VERSION 5.8 ;
BUSBITCHARS "[]" ;
DIVIDERCHAR "/" ;
UNITS
    DATABASE MICRONS 1000 ;
END UNITS

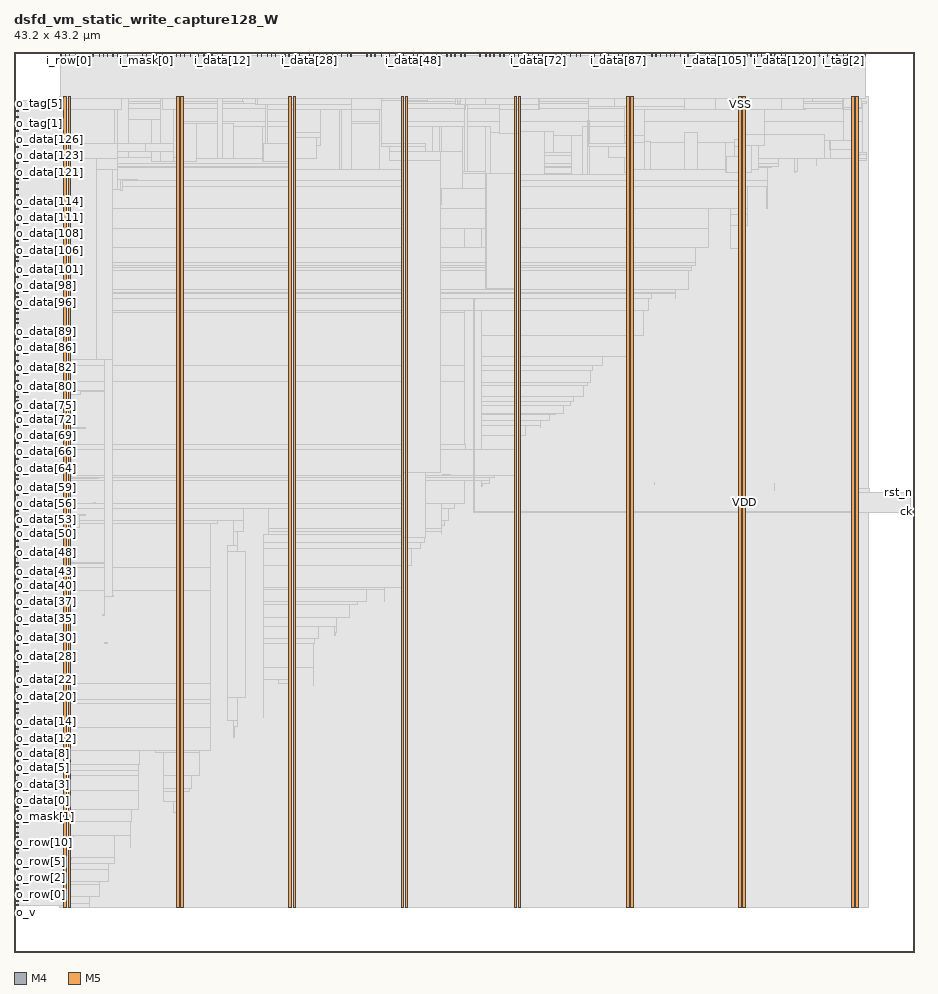
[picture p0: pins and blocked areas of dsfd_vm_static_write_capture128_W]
MACRO dsfd_vm_static_write_capture128_W
  FOREIGN dsfd_vm_static_write_capture128_W 0 0 ;
  CLASS BLOCK ;
  SIZE 43.2 BY 43.2 ;
  PIN ck
    DIRECTION INPUT ;
    USE SIGNAL ;
    PORT
      LAYER M4 ;
        RECT  43.008 21.12 43.2 21.144 ;
    END
  END ck
  PIN i_data[0]
    DIRECTION INPUT ;
    USE SIGNAL ;
    PORT
      LAYER M5 ;
        RECT  7.296 43.008 7.32 43.2 ;
    END
  END i_data[0]
  PIN i_data[100]
    DIRECTION INPUT ;
    USE SIGNAL ;
    PORT
      LAYER M5 ;
        RECT  31.968 43.008 31.992 43.2 ;
    END
  END i_data[100]
  PIN i_data[101]
    DIRECTION INPUT ;
    USE SIGNAL ;
    PORT
      LAYER M5 ;
        RECT  32.16 43.008 32.184 43.2 ;
    END
  END i_data[101]
  PIN i_data[102]
    DIRECTION INPUT ;
    USE SIGNAL ;
    PORT
      LAYER M5 ;
        RECT  32.352 43.008 32.376 43.2 ;
    END
  END i_data[102]
  PIN i_data[103]
    DIRECTION INPUT ;
    USE SIGNAL ;
    PORT
      LAYER M5 ;
        RECT  33.168 43.008 33.192 43.2 ;
    END
  END i_data[103]
  PIN i_data[104]
    DIRECTION INPUT ;
    USE SIGNAL ;
    PORT
      LAYER M5 ;
        RECT  33.36 43.008 33.384 43.2 ;
    END
  END i_data[104]
  PIN i_data[105]
    DIRECTION INPUT ;
    USE SIGNAL ;
    PORT
      LAYER M5 ;
        RECT  33.648 43.008 33.672 43.2 ;
    END
  END i_data[105]
  PIN i_data[106]
    DIRECTION INPUT ;
    USE SIGNAL ;
    PORT
      LAYER M5 ;
        RECT  33.84 43.008 33.864 43.2 ;
    END
  END i_data[106]
  PIN i_data[107]
    DIRECTION INPUT ;
    USE SIGNAL ;
    PORT
      LAYER M5 ;
        RECT  34.032 43.008 34.056 43.2 ;
    END
  END i_data[107]
  PIN i_data[108]
    DIRECTION INPUT ;
    USE SIGNAL ;
    PORT
      LAYER M5 ;
        RECT  34.32 43.008 34.344 43.2 ;
    END
  END i_data[108]
  PIN i_data[109]
    DIRECTION INPUT ;
    USE SIGNAL ;
    PORT
      LAYER M5 ;
        RECT  34.512 43.008 34.536 43.2 ;
    END
  END i_data[109]
  PIN i_data[10]
    DIRECTION INPUT ;
    USE SIGNAL ;
    PORT
      LAYER M5 ;
        RECT  9.504 43.008 9.528 43.2 ;
    END
  END i_data[10]
  PIN i_data[110]
    DIRECTION INPUT ;
    USE SIGNAL ;
    PORT
      LAYER M5 ;
        RECT  34.704 43.008 34.728 43.2 ;
    END
  END i_data[110]
  PIN i_data[111]
    DIRECTION INPUT ;
    USE SIGNAL ;
    PORT
      LAYER M5 ;
        RECT  34.992 43.008 35.016 43.2 ;
    END
  END i_data[111]
  PIN i_data[112]
    DIRECTION INPUT ;
    USE SIGNAL ;
    PORT
      LAYER M5 ;
        RECT  35.184 43.008 35.208 43.2 ;
    END
  END i_data[112]
  PIN i_data[113]
    DIRECTION INPUT ;
    USE SIGNAL ;
    PORT
      LAYER M5 ;
        RECT  35.376 43.008 35.4 43.2 ;
    END
  END i_data[113]
  PIN i_data[114]
    DIRECTION INPUT ;
    USE SIGNAL ;
    PORT
      LAYER M5 ;
        RECT  35.664 43.008 35.688 43.2 ;
    END
  END i_data[114]
  PIN i_data[115]
    DIRECTION INPUT ;
    USE SIGNAL ;
    PORT
      LAYER M5 ;
        RECT  35.856 43.008 35.88 43.2 ;
    END
  END i_data[115]
  PIN i_data[116]
    DIRECTION INPUT ;
    USE SIGNAL ;
    PORT
      LAYER M5 ;
        RECT  36.144 43.008 36.168 43.2 ;
    END
  END i_data[116]
  PIN i_data[117]
    DIRECTION INPUT ;
    USE SIGNAL ;
    PORT
      LAYER M5 ;
        RECT  36.336 43.008 36.36 43.2 ;
    END
  END i_data[117]
  PIN i_data[118]
    DIRECTION INPUT ;
    USE SIGNAL ;
    PORT
      LAYER M5 ;
        RECT  36.528 43.008 36.552 43.2 ;
    END
  END i_data[118]
  PIN i_data[119]
    DIRECTION INPUT ;
    USE SIGNAL ;
    PORT
      LAYER M5 ;
        RECT  36.816 43.008 36.84 43.2 ;
    END
  END i_data[119]
  PIN i_data[11]
    DIRECTION INPUT ;
    USE SIGNAL ;
    PORT
      LAYER M5 ;
        RECT  9.792 43.008 9.816 43.2 ;
    END
  END i_data[11]
  PIN i_data[120]
    DIRECTION INPUT ;
    USE SIGNAL ;
    PORT
      LAYER M5 ;
        RECT  37.008 43.008 37.032 43.2 ;
    END
  END i_data[120]
  PIN i_data[121]
    DIRECTION INPUT ;
    USE SIGNAL ;
    PORT
      LAYER M5 ;
        RECT  37.2 43.008 37.224 43.2 ;
    END
  END i_data[121]
  PIN i_data[122]
    DIRECTION INPUT ;
    USE SIGNAL ;
    PORT
      LAYER M5 ;
        RECT  37.488 43.008 37.512 43.2 ;
    END
  END i_data[122]
  PIN i_data[123]
    DIRECTION INPUT ;
    USE SIGNAL ;
    PORT
      LAYER M5 ;
        RECT  37.68 43.008 37.704 43.2 ;
    END
  END i_data[123]
  PIN i_data[124]
    DIRECTION INPUT ;
    USE SIGNAL ;
    PORT
      LAYER M5 ;
        RECT  37.872 43.008 37.896 43.2 ;
    END
  END i_data[124]
  PIN i_data[125]
    DIRECTION INPUT ;
    USE SIGNAL ;
    PORT
      LAYER M5 ;
        RECT  38.64 43.008 38.664 43.2 ;
    END
  END i_data[125]
  PIN i_data[126]
    DIRECTION INPUT ;
    USE SIGNAL ;
    PORT
      LAYER M5 ;
        RECT  38.832 43.008 38.856 43.2 ;
    END
  END i_data[126]
  PIN i_data[127]
    DIRECTION INPUT ;
    USE SIGNAL ;
    PORT
      LAYER M5 ;
        RECT  39.024 43.008 39.048 43.2 ;
    END
  END i_data[127]
  PIN i_data[12]
    DIRECTION INPUT ;
    USE SIGNAL ;
    PORT
      LAYER M5 ;
        RECT  9.984 43.008 10.008 43.2 ;
    END
  END i_data[12]
  PIN i_data[13]
    DIRECTION INPUT ;
    USE SIGNAL ;
    PORT
      LAYER M5 ;
        RECT  10.272 43.008 10.296 43.2 ;
    END
  END i_data[13]
  PIN i_data[14]
    DIRECTION INPUT ;
    USE SIGNAL ;
    PORT
      LAYER M5 ;
        RECT  10.464 43.008 10.488 43.2 ;
    END
  END i_data[14]
  PIN i_data[15]
    DIRECTION INPUT ;
    USE SIGNAL ;
    PORT
      LAYER M5 ;
        RECT  10.656 43.008 10.68 43.2 ;
    END
  END i_data[15]
  PIN i_data[16]
    DIRECTION INPUT ;
    USE SIGNAL ;
    PORT
      LAYER M5 ;
        RECT  10.944 43.008 10.968 43.2 ;
    END
  END i_data[16]
  PIN i_data[17]
    DIRECTION INPUT ;
    USE SIGNAL ;
    PORT
      LAYER M5 ;
        RECT  11.664 43.008 11.688 43.2 ;
    END
  END i_data[17]
  PIN i_data[18]
    DIRECTION INPUT ;
    USE SIGNAL ;
    PORT
      LAYER M5 ;
        RECT  11.856 43.008 11.88 43.2 ;
    END
  END i_data[18]
  PIN i_data[19]
    DIRECTION INPUT ;
    USE SIGNAL ;
    PORT
      LAYER M5 ;
        RECT  12.144 43.008 12.168 43.2 ;
    END
  END i_data[19]
  PIN i_data[1]
    DIRECTION INPUT ;
    USE SIGNAL ;
    PORT
      LAYER M5 ;
        RECT  7.488 43.008 7.512 43.2 ;
    END
  END i_data[1]
  PIN i_data[20]
    DIRECTION INPUT ;
    USE SIGNAL ;
    PORT
      LAYER M5 ;
        RECT  12.336 43.008 12.36 43.2 ;
    END
  END i_data[20]
  PIN i_data[21]
    DIRECTION INPUT ;
    USE SIGNAL ;
    PORT
      LAYER M5 ;
        RECT  12.528 43.008 12.552 43.2 ;
    END
  END i_data[21]
  PIN i_data[22]
    DIRECTION INPUT ;
    USE SIGNAL ;
    PORT
      LAYER M5 ;
        RECT  12.816 43.008 12.84 43.2 ;
    END
  END i_data[22]
  PIN i_data[23]
    DIRECTION INPUT ;
    USE SIGNAL ;
    PORT
      LAYER M5 ;
        RECT  13.008 43.008 13.032 43.2 ;
    END
  END i_data[23]
  PIN i_data[24]
    DIRECTION INPUT ;
    USE SIGNAL ;
    PORT
      LAYER M5 ;
        RECT  13.2 43.008 13.224 43.2 ;
    END
  END i_data[24]
  PIN i_data[25]
    DIRECTION INPUT ;
    USE SIGNAL ;
    PORT
      LAYER M5 ;
        RECT  13.488 43.008 13.512 43.2 ;
    END
  END i_data[25]
  PIN i_data[26]
    DIRECTION INPUT ;
    USE SIGNAL ;
    PORT
      LAYER M5 ;
        RECT  13.68 43.008 13.704 43.2 ;
    END
  END i_data[26]
  PIN i_data[27]
    DIRECTION INPUT ;
    USE SIGNAL ;
    PORT
      LAYER M5 ;
        RECT  13.968 43.008 13.992 43.2 ;
    END
  END i_data[27]
  PIN i_data[28]
    DIRECTION INPUT ;
    USE SIGNAL ;
    PORT
      LAYER M5 ;
        RECT  14.16 43.008 14.184 43.2 ;
    END
  END i_data[28]
  PIN i_data[29]
    DIRECTION INPUT ;
    USE SIGNAL ;
    PORT
      LAYER M5 ;
        RECT  14.352 43.008 14.376 43.2 ;
    END
  END i_data[29]
  PIN i_data[2]
    DIRECTION INPUT ;
    USE SIGNAL ;
    PORT
      LAYER M5 ;
        RECT  7.776 43.008 7.8 43.2 ;
    END
  END i_data[2]
  PIN i_data[30]
    DIRECTION INPUT ;
    USE SIGNAL ;
    PORT
      LAYER M5 ;
        RECT  14.64 43.008 14.664 43.2 ;
    END
  END i_data[30]
  PIN i_data[31]
    DIRECTION INPUT ;
    USE SIGNAL ;
    PORT
      LAYER M5 ;
        RECT  14.832 43.008 14.856 43.2 ;
    END
  END i_data[31]
  PIN i_data[32]
    DIRECTION INPUT ;
    USE SIGNAL ;
    PORT
      LAYER M5 ;
        RECT  15.024 43.008 15.048 43.2 ;
    END
  END i_data[32]
  PIN i_data[33]
    DIRECTION INPUT ;
    USE SIGNAL ;
    PORT
      LAYER M5 ;
        RECT  15.312 43.008 15.336 43.2 ;
    END
  END i_data[33]
  PIN i_data[34]
    DIRECTION INPUT ;
    USE SIGNAL ;
    PORT
      LAYER M5 ;
        RECT  15.504 43.008 15.528 43.2 ;
    END
  END i_data[34]
  PIN i_data[35]
    DIRECTION INPUT ;
    USE SIGNAL ;
    PORT
      LAYER M5 ;
        RECT  15.696 43.008 15.72 43.2 ;
    END
  END i_data[35]
  PIN i_data[36]
    DIRECTION INPUT ;
    USE SIGNAL ;
    PORT
      LAYER M5 ;
        RECT  15.984 43.008 16.008 43.2 ;
    END
  END i_data[36]
  PIN i_data[37]
    DIRECTION INPUT ;
    USE SIGNAL ;
    PORT
      LAYER M5 ;
        RECT  16.176 43.008 16.2 43.2 ;
    END
  END i_data[37]
  PIN i_data[38]
    DIRECTION INPUT ;
    USE SIGNAL ;
    PORT
      LAYER M5 ;
        RECT  16.944 43.008 16.968 43.2 ;
    END
  END i_data[38]
  PIN i_data[39]
    DIRECTION INPUT ;
    USE SIGNAL ;
    PORT
      LAYER M5 ;
        RECT  17.136 43.008 17.16 43.2 ;
    END
  END i_data[39]
  PIN i_data[3]
    DIRECTION INPUT ;
    USE SIGNAL ;
    PORT
      LAYER M5 ;
        RECT  7.968 43.008 7.992 43.2 ;
    END
  END i_data[3]
  PIN i_data[40]
    DIRECTION INPUT ;
    USE SIGNAL ;
    PORT
      LAYER M5 ;
        RECT  17.328 43.008 17.352 43.2 ;
    END
  END i_data[40]
  PIN i_data[41]
    DIRECTION INPUT ;
    USE SIGNAL ;
    PORT
      LAYER M5 ;
        RECT  17.616 43.008 17.64 43.2 ;
    END
  END i_data[41]
  PIN i_data[42]
    DIRECTION INPUT ;
    USE SIGNAL ;
    PORT
      LAYER M5 ;
        RECT  17.808 43.008 17.832 43.2 ;
    END
  END i_data[42]
  PIN i_data[43]
    DIRECTION INPUT ;
    USE SIGNAL ;
    PORT
      LAYER M5 ;
        RECT  18 43.008 18.024 43.2 ;
    END
  END i_data[43]
  PIN i_data[44]
    DIRECTION INPUT ;
    USE SIGNAL ;
    PORT
      LAYER M5 ;
        RECT  18.288 43.008 18.312 43.2 ;
    END
  END i_data[44]
  PIN i_data[45]
    DIRECTION INPUT ;
    USE SIGNAL ;
    PORT
      LAYER M5 ;
        RECT  18.48 43.008 18.504 43.2 ;
    END
  END i_data[45]
  PIN i_data[46]
    DIRECTION INPUT ;
    USE SIGNAL ;
    PORT
      LAYER M5 ;
        RECT  18.672 43.008 18.696 43.2 ;
    END
  END i_data[46]
  PIN i_data[47]
    DIRECTION INPUT ;
    USE SIGNAL ;
    PORT
      LAYER M5 ;
        RECT  18.96 43.008 18.984 43.2 ;
    END
  END i_data[47]
  PIN i_data[48]
    DIRECTION INPUT ;
    USE SIGNAL ;
    PORT
      LAYER M5 ;
        RECT  19.152 43.008 19.176 43.2 ;
    END
  END i_data[48]
  PIN i_data[49]
    DIRECTION INPUT ;
    USE SIGNAL ;
    PORT
      LAYER M5 ;
        RECT  19.344 43.008 19.368 43.2 ;
    END
  END i_data[49]
  PIN i_data[4]
    DIRECTION INPUT ;
    USE SIGNAL ;
    PORT
      LAYER M5 ;
        RECT  8.16 43.008 8.184 43.2 ;
    END
  END i_data[4]
  PIN i_data[50]
    DIRECTION INPUT ;
    USE SIGNAL ;
    PORT
      LAYER M5 ;
        RECT  19.632 43.008 19.656 43.2 ;
    END
  END i_data[50]
  PIN i_data[51]
    DIRECTION INPUT ;
    USE SIGNAL ;
    PORT
      LAYER M5 ;
        RECT  19.824 43.008 19.848 43.2 ;
    END
  END i_data[51]
  PIN i_data[52]
    DIRECTION INPUT ;
    USE SIGNAL ;
    PORT
      LAYER M5 ;
        RECT  20.112 43.008 20.136 43.2 ;
    END
  END i_data[52]
  PIN i_data[53]
    DIRECTION INPUT ;
    USE SIGNAL ;
    PORT
      LAYER M5 ;
        RECT  20.304 43.008 20.328 43.2 ;
    END
  END i_data[53]
  PIN i_data[54]
    DIRECTION INPUT ;
    USE SIGNAL ;
    PORT
      LAYER M5 ;
        RECT  20.496 43.008 20.52 43.2 ;
    END
  END i_data[54]
  PIN i_data[55]
    DIRECTION INPUT ;
    USE SIGNAL ;
    PORT
      LAYER M5 ;
        RECT  20.784 43.008 20.808 43.2 ;
    END
  END i_data[55]
  PIN i_data[56]
    DIRECTION INPUT ;
    USE SIGNAL ;
    PORT
      LAYER M5 ;
        RECT  20.976 43.008 21 43.2 ;
    END
  END i_data[56]
  PIN i_data[57]
    DIRECTION INPUT ;
    USE SIGNAL ;
    PORT
      LAYER M5 ;
        RECT  21.168 43.008 21.192 43.2 ;
    END
  END i_data[57]
  PIN i_data[58]
    DIRECTION INPUT ;
    USE SIGNAL ;
    PORT
      LAYER M5 ;
        RECT  21.456 43.008 21.48 43.2 ;
    END
  END i_data[58]
  PIN i_data[59]
    DIRECTION INPUT ;
    USE SIGNAL ;
    PORT
      LAYER M5 ;
        RECT  21.648 43.008 21.672 43.2 ;
    END
  END i_data[59]
  PIN i_data[5]
    DIRECTION INPUT ;
    USE SIGNAL ;
    PORT
      LAYER M5 ;
        RECT  8.448 43.008 8.472 43.2 ;
    END
  END i_data[5]
  PIN i_data[60]
    DIRECTION INPUT ;
    USE SIGNAL ;
    PORT
      LAYER M5 ;
        RECT  22.368 43.008 22.392 43.2 ;
    END
  END i_data[60]
  PIN i_data[61]
    DIRECTION INPUT ;
    USE SIGNAL ;
    PORT
      LAYER M5 ;
        RECT  22.656 43.008 22.68 43.2 ;
    END
  END i_data[61]
  PIN i_data[62]
    DIRECTION INPUT ;
    USE SIGNAL ;
    PORT
      LAYER M5 ;
        RECT  22.848 43.008 22.872 43.2 ;
    END
  END i_data[62]
  PIN i_data[63]
    DIRECTION INPUT ;
    USE SIGNAL ;
    PORT
      LAYER M5 ;
        RECT  23.04 43.008 23.064 43.2 ;
    END
  END i_data[63]
  PIN i_data[64]
    DIRECTION INPUT ;
    USE SIGNAL ;
    PORT
      LAYER M5 ;
        RECT  23.328 43.008 23.352 43.2 ;
    END
  END i_data[64]
  PIN i_data[65]
    DIRECTION INPUT ;
    USE SIGNAL ;
    PORT
      LAYER M5 ;
        RECT  23.52 43.008 23.544 43.2 ;
    END
  END i_data[65]
  PIN i_data[66]
    DIRECTION INPUT ;
    USE SIGNAL ;
    PORT
      LAYER M5 ;
        RECT  23.808 43.008 23.832 43.2 ;
    END
  END i_data[66]
  PIN i_data[67]
    DIRECTION INPUT ;
    USE SIGNAL ;
    PORT
      LAYER M5 ;
        RECT  24 43.008 24.024 43.2 ;
    END
  END i_data[67]
  PIN i_data[68]
    DIRECTION INPUT ;
    USE SIGNAL ;
    PORT
      LAYER M5 ;
        RECT  24.192 43.008 24.216 43.2 ;
    END
  END i_data[68]
  PIN i_data[69]
    DIRECTION INPUT ;
    USE SIGNAL ;
    PORT
      LAYER M5 ;
        RECT  24.48 43.008 24.504 43.2 ;
    END
  END i_data[69]
  PIN i_data[6]
    DIRECTION INPUT ;
    USE SIGNAL ;
    PORT
      LAYER M5 ;
        RECT  8.64 43.008 8.664 43.2 ;
    END
  END i_data[6]
  PIN i_data[70]
    DIRECTION INPUT ;
    USE SIGNAL ;
    PORT
      LAYER M5 ;
        RECT  24.672 43.008 24.696 43.2 ;
    END
  END i_data[70]
  PIN i_data[71]
    DIRECTION INPUT ;
    USE SIGNAL ;
    PORT
      LAYER M5 ;
        RECT  24.864 43.008 24.888 43.2 ;
    END
  END i_data[71]
  PIN i_data[72]
    DIRECTION INPUT ;
    USE SIGNAL ;
    PORT
      LAYER M5 ;
        RECT  25.152 43.008 25.176 43.2 ;
    END
  END i_data[72]
  PIN i_data[73]
    DIRECTION INPUT ;
    USE SIGNAL ;
    PORT
      LAYER M5 ;
        RECT  25.344 43.008 25.368 43.2 ;
    END
  END i_data[73]
  PIN i_data[74]
    DIRECTION INPUT ;
    USE SIGNAL ;
    PORT
      LAYER M5 ;
        RECT  25.536 43.008 25.56 43.2 ;
    END
  END i_data[74]
  PIN i_data[75]
    DIRECTION INPUT ;
    USE SIGNAL ;
    PORT
      LAYER M5 ;
        RECT  25.824 43.008 25.848 43.2 ;
    END
  END i_data[75]
  PIN i_data[76]
    DIRECTION INPUT ;
    USE SIGNAL ;
    PORT
      LAYER M5 ;
        RECT  26.016 43.008 26.04 43.2 ;
    END
  END i_data[76]
  PIN i_data[77]
    DIRECTION INPUT ;
    USE SIGNAL ;
    PORT
      LAYER M5 ;
        RECT  26.304 43.008 26.328 43.2 ;
    END
  END i_data[77]
  PIN i_data[78]
    DIRECTION INPUT ;
    USE SIGNAL ;
    PORT
      LAYER M5 ;
        RECT  26.496 43.008 26.52 43.2 ;
    END
  END i_data[78]
  PIN i_data[79]
    DIRECTION INPUT ;
    USE SIGNAL ;
    PORT
      LAYER M5 ;
        RECT  26.688 43.008 26.712 43.2 ;
    END
  END i_data[79]
  PIN i_data[7]
    DIRECTION INPUT ;
    USE SIGNAL ;
    PORT
      LAYER M5 ;
        RECT  8.832 43.008 8.856 43.2 ;
    END
  END i_data[7]
  PIN i_data[80]
    DIRECTION INPUT ;
    USE SIGNAL ;
    PORT
      LAYER M5 ;
        RECT  26.976 43.008 27 43.2 ;
    END
  END i_data[80]
  PIN i_data[81]
    DIRECTION INPUT ;
    USE SIGNAL ;
    PORT
      LAYER M5 ;
        RECT  27.168 43.008 27.192 43.2 ;
    END
  END i_data[81]
  PIN i_data[82]
    DIRECTION INPUT ;
    USE SIGNAL ;
    PORT
      LAYER M5 ;
        RECT  27.84 43.008 27.864 43.2 ;
    END
  END i_data[82]
  PIN i_data[83]
    DIRECTION INPUT ;
    USE SIGNAL ;
    PORT
      LAYER M5 ;
        RECT  28.128 43.008 28.152 43.2 ;
    END
  END i_data[83]
  PIN i_data[84]
    DIRECTION INPUT ;
    USE SIGNAL ;
    PORT
      LAYER M5 ;
        RECT  28.32 43.008 28.344 43.2 ;
    END
  END i_data[84]
  PIN i_data[85]
    DIRECTION INPUT ;
    USE SIGNAL ;
    PORT
      LAYER M5 ;
        RECT  28.512 43.008 28.536 43.2 ;
    END
  END i_data[85]
  PIN i_data[86]
    DIRECTION INPUT ;
    USE SIGNAL ;
    PORT
      LAYER M5 ;
        RECT  28.8 43.008 28.824 43.2 ;
    END
  END i_data[86]
  PIN i_data[87]
    DIRECTION INPUT ;
    USE SIGNAL ;
    PORT
      LAYER M5 ;
        RECT  28.992 43.008 29.016 43.2 ;
    END
  END i_data[87]
  PIN i_data[88]
    DIRECTION INPUT ;
    USE SIGNAL ;
    PORT
      LAYER M5 ;
        RECT  29.184 43.008 29.208 43.2 ;
    END
  END i_data[88]
  PIN i_data[89]
    DIRECTION INPUT ;
    USE SIGNAL ;
    PORT
      LAYER M5 ;
        RECT  29.472 43.008 29.496 43.2 ;
    END
  END i_data[89]
  PIN i_data[8]
    DIRECTION INPUT ;
    USE SIGNAL ;
    PORT
      LAYER M5 ;
        RECT  9.12 43.008 9.144 43.2 ;
    END
  END i_data[8]
  PIN i_data[90]
    DIRECTION INPUT ;
    USE SIGNAL ;
    PORT
      LAYER M5 ;
        RECT  29.664 43.008 29.688 43.2 ;
    END
  END i_data[90]
  PIN i_data[91]
    DIRECTION INPUT ;
    USE SIGNAL ;
    PORT
      LAYER M5 ;
        RECT  29.952 43.008 29.976 43.2 ;
    END
  END i_data[91]
  PIN i_data[92]
    DIRECTION INPUT ;
    USE SIGNAL ;
    PORT
      LAYER M5 ;
        RECT  30.144 43.008 30.168 43.2 ;
    END
  END i_data[92]
  PIN i_data[93]
    DIRECTION INPUT ;
    USE SIGNAL ;
    PORT
      LAYER M5 ;
        RECT  30.336 43.008 30.36 43.2 ;
    END
  END i_data[93]
  PIN i_data[94]
    DIRECTION INPUT ;
    USE SIGNAL ;
    PORT
      LAYER M5 ;
        RECT  30.624 43.008 30.648 43.2 ;
    END
  END i_data[94]
  PIN i_data[95]
    DIRECTION INPUT ;
    USE SIGNAL ;
    PORT
      LAYER M5 ;
        RECT  30.816 43.008 30.84 43.2 ;
    END
  END i_data[95]
  PIN i_data[96]
    DIRECTION INPUT ;
    USE SIGNAL ;
    PORT
      LAYER M5 ;
        RECT  31.008 43.008 31.032 43.2 ;
    END
  END i_data[96]
  PIN i_data[97]
    DIRECTION INPUT ;
    USE SIGNAL ;
    PORT
      LAYER M5 ;
        RECT  31.296 43.008 31.32 43.2 ;
    END
  END i_data[97]
  PIN i_data[98]
    DIRECTION INPUT ;
    USE SIGNAL ;
    PORT
      LAYER M5 ;
        RECT  31.488 43.008 31.512 43.2 ;
    END
  END i_data[98]
  PIN i_data[99]
    DIRECTION INPUT ;
    USE SIGNAL ;
    PORT
      LAYER M5 ;
        RECT  31.68 43.008 31.704 43.2 ;
    END
  END i_data[99]
  PIN i_data[9]
    DIRECTION INPUT ;
    USE SIGNAL ;
    PORT
      LAYER M5 ;
        RECT  9.312 43.008 9.336 43.2 ;
    END
  END i_data[9]
  PIN i_mask[0]
    DIRECTION INPUT ;
    USE SIGNAL ;
    PORT
      LAYER M5 ;
        RECT  6.336 43.008 6.36 43.2 ;
    END
  END i_mask[0]
  PIN i_mask[1]
    DIRECTION INPUT ;
    USE SIGNAL ;
    PORT
      LAYER M5 ;
        RECT  6.624 43.008 6.648 43.2 ;
    END
  END i_mask[1]
  PIN i_mask[2]
    DIRECTION INPUT ;
    USE SIGNAL ;
    PORT
      LAYER M5 ;
        RECT  6.816 43.008 6.84 43.2 ;
    END
  END i_mask[2]
  PIN i_mask[3]
    DIRECTION INPUT ;
    USE SIGNAL ;
    PORT
      LAYER M5 ;
        RECT  7.104 43.008 7.128 43.2 ;
    END
  END i_mask[3]
  PIN i_row[0]
    DIRECTION INPUT ;
    USE SIGNAL ;
    PORT
      LAYER M5 ;
        RECT  2.64 43.008 2.664 43.2 ;
    END
  END i_row[0]
  PIN i_row[10]
    DIRECTION INPUT ;
    USE SIGNAL ;
    PORT
      LAYER M5 ;
        RECT  4.944 43.008 4.968 43.2 ;
    END
  END i_row[10]
  PIN i_row[11]
    DIRECTION INPUT ;
    USE SIGNAL ;
    PORT
      LAYER M5 ;
        RECT  5.136 43.008 5.16 43.2 ;
    END
  END i_row[11]
  PIN i_row[12]
    DIRECTION INPUT ;
    USE SIGNAL ;
    PORT
      LAYER M5 ;
        RECT  5.424 43.008 5.448 43.2 ;
    END
  END i_row[12]
  PIN i_row[13]
    DIRECTION INPUT ;
    USE SIGNAL ;
    PORT
      LAYER M5 ;
        RECT  6.144 43.008 6.168 43.2 ;
    END
  END i_row[13]
  PIN i_row[1]
    DIRECTION INPUT ;
    USE SIGNAL ;
    PORT
      LAYER M5 ;
        RECT  2.928 43.008 2.952 43.2 ;
    END
  END i_row[1]
  PIN i_row[2]
    DIRECTION INPUT ;
    USE SIGNAL ;
    PORT
      LAYER M5 ;
        RECT  3.12 43.008 3.144 43.2 ;
    END
  END i_row[2]
  PIN i_row[3]
    DIRECTION INPUT ;
    USE SIGNAL ;
    PORT
      LAYER M5 ;
        RECT  3.312 43.008 3.336 43.2 ;
    END
  END i_row[3]
  PIN i_row[4]
    DIRECTION INPUT ;
    USE SIGNAL ;
    PORT
      LAYER M5 ;
        RECT  3.6 43.008 3.624 43.2 ;
    END
  END i_row[4]
  PIN i_row[5]
    DIRECTION INPUT ;
    USE SIGNAL ;
    PORT
      LAYER M5 ;
        RECT  3.792 43.008 3.816 43.2 ;
    END
  END i_row[5]
  PIN i_row[6]
    DIRECTION INPUT ;
    USE SIGNAL ;
    PORT
      LAYER M5 ;
        RECT  4.08 43.008 4.104 43.2 ;
    END
  END i_row[6]
  PIN i_row[7]
    DIRECTION INPUT ;
    USE SIGNAL ;
    PORT
      LAYER M5 ;
        RECT  4.272 43.008 4.296 43.2 ;
    END
  END i_row[7]
  PIN i_row[8]
    DIRECTION INPUT ;
    USE SIGNAL ;
    PORT
      LAYER M5 ;
        RECT  4.464 43.008 4.488 43.2 ;
    END
  END i_row[8]
  PIN i_row[9]
    DIRECTION INPUT ;
    USE SIGNAL ;
    PORT
      LAYER M5 ;
        RECT  4.752 43.008 4.776 43.2 ;
    END
  END i_row[9]
  PIN i_tag[0]
    DIRECTION INPUT ;
    USE SIGNAL ;
    PORT
      LAYER M5 ;
        RECT  39.312 43.008 39.336 43.2 ;
    END
  END i_tag[0]
  PIN i_tag[1]
    DIRECTION INPUT ;
    USE SIGNAL ;
    PORT
      LAYER M5 ;
        RECT  39.504 43.008 39.528 43.2 ;
    END
  END i_tag[1]
  PIN i_tag[2]
    DIRECTION INPUT ;
    USE SIGNAL ;
    PORT
      LAYER M5 ;
        RECT  39.792 43.008 39.816 43.2 ;
    END
  END i_tag[2]
  PIN i_tag[3]
    DIRECTION INPUT ;
    USE SIGNAL ;
    PORT
      LAYER M5 ;
        RECT  39.984 43.008 40.008 43.2 ;
    END
  END i_tag[3]
  PIN i_tag[4]
    DIRECTION INPUT ;
    USE SIGNAL ;
    PORT
      LAYER M5 ;
        RECT  40.176 43.008 40.2 43.2 ;
    END
  END i_tag[4]
  PIN i_tag[5]
    DIRECTION INPUT ;
    USE SIGNAL ;
    PORT
      LAYER M5 ;
        RECT  40.464 43.008 40.488 43.2 ;
    END
  END i_tag[5]
  PIN i_tag[6]
    DIRECTION INPUT ;
    USE SIGNAL ;
    PORT
      LAYER M5 ;
        RECT  40.656 43.008 40.68 43.2 ;
    END
  END i_tag[6]
  PIN i_tag[7]
    DIRECTION INPUT ;
    USE SIGNAL ;
    PORT
      LAYER M5 ;
        RECT  40.848 43.008 40.872 43.2 ;
    END
  END i_tag[7]
  PIN i_v
    DIRECTION INPUT ;
    USE SIGNAL ;
    PORT
      LAYER M5 ;
        RECT  2.256 43.008 2.28 43.2 ;
    END
  END i_v
  PIN i_we
    DIRECTION INPUT ;
    USE SIGNAL ;
    PORT
      LAYER M5 ;
        RECT  2.448 43.008 2.472 43.2 ;
    END
  END i_we
  PIN o_data[0]
    DIRECTION OUTPUT ;
    USE SIGNAL ;
    PORT
      LAYER M4 ;
        RECT  0 7.248 0.192 7.272 ;
    END
  END o_data[0]
  PIN o_data[100]
    DIRECTION OUTPUT ;
    USE SIGNAL ;
    PORT
      LAYER M4 ;
        RECT  0 32.112 0.192 32.136 ;
    END
  END o_data[100]
  PIN o_data[101]
    DIRECTION OUTPUT ;
    USE SIGNAL ;
    PORT
      LAYER M4 ;
        RECT  0 32.4 0.192 32.424 ;
    END
  END o_data[101]
  PIN o_data[102]
    DIRECTION OUTPUT ;
    USE SIGNAL ;
    PORT
      LAYER M4 ;
        RECT  0 32.688 0.192 32.712 ;
    END
  END o_data[102]
  PIN o_data[103]
    DIRECTION OUTPUT ;
    USE SIGNAL ;
    PORT
      LAYER M4 ;
        RECT  0 32.88 0.192 32.904 ;
    END
  END o_data[103]
  PIN o_data[104]
    DIRECTION OUTPUT ;
    USE SIGNAL ;
    PORT
      LAYER M4 ;
        RECT  0 33.168 0.192 33.192 ;
    END
  END o_data[104]
  PIN o_data[105]
    DIRECTION OUTPUT ;
    USE SIGNAL ;
    PORT
      LAYER M4 ;
        RECT  0 33.36 0.192 33.384 ;
    END
  END o_data[105]
  PIN o_data[106]
    DIRECTION OUTPUT ;
    USE SIGNAL ;
    PORT
      LAYER M4 ;
        RECT  0 33.648 0.192 33.672 ;
    END
  END o_data[106]
  PIN o_data[107]
    DIRECTION OUTPUT ;
    USE SIGNAL ;
    PORT
      LAYER M4 ;
        RECT  0 33.936 0.192 33.96 ;
    END
  END o_data[107]
  PIN o_data[108]
    DIRECTION OUTPUT ;
    USE SIGNAL ;
    PORT
      LAYER M4 ;
        RECT  0 34.128 0.192 34.152 ;
    END
  END o_data[108]
  PIN o_data[109]
    DIRECTION OUTPUT ;
    USE SIGNAL ;
    PORT
      LAYER M4 ;
        RECT  0 34.416 0.192 34.44 ;
    END
  END o_data[109]
  PIN o_data[10]
    DIRECTION OUTPUT ;
    USE SIGNAL ;
    PORT
      LAYER M4 ;
        RECT  0 9.744 0.192 9.768 ;
    END
  END o_data[10]
  PIN o_data[110]
    DIRECTION OUTPUT ;
    USE SIGNAL ;
    PORT
      LAYER M4 ;
        RECT  0 34.608 0.192 34.632 ;
    END
  END o_data[110]
  PIN o_data[111]
    DIRECTION OUTPUT ;
    USE SIGNAL ;
    PORT
      LAYER M4 ;
        RECT  0 34.896 0.192 34.92 ;
    END
  END o_data[111]
  PIN o_data[112]
    DIRECTION OUTPUT ;
    USE SIGNAL ;
    PORT
      LAYER M4 ;
        RECT  0 35.088 0.192 35.112 ;
    END
  END o_data[112]
  PIN o_data[113]
    DIRECTION OUTPUT ;
    USE SIGNAL ;
    PORT
      LAYER M4 ;
        RECT  0 35.376 0.192 35.4 ;
    END
  END o_data[113]
  PIN o_data[114]
    DIRECTION OUTPUT ;
    USE SIGNAL ;
    PORT
      LAYER M4 ;
        RECT  0 35.664 0.192 35.688 ;
    END
  END o_data[114]
  PIN o_data[115]
    DIRECTION OUTPUT ;
    USE SIGNAL ;
    PORT
      LAYER M4 ;
        RECT  0 35.856 0.192 35.88 ;
    END
  END o_data[115]
  PIN o_data[116]
    DIRECTION OUTPUT ;
    USE SIGNAL ;
    PORT
      LAYER M4 ;
        RECT  0 36.144 0.192 36.168 ;
    END
  END o_data[116]
  PIN o_data[117]
    DIRECTION OUTPUT ;
    USE SIGNAL ;
    PORT
      LAYER M4 ;
        RECT  0 36.336 0.192 36.36 ;
    END
  END o_data[117]
  PIN o_data[118]
    DIRECTION OUTPUT ;
    USE SIGNAL ;
    PORT
      LAYER M4 ;
        RECT  0 36.624 0.192 36.648 ;
    END
  END o_data[118]
  PIN o_data[119]
    DIRECTION OUTPUT ;
    USE SIGNAL ;
    PORT
      LAYER M4 ;
        RECT  0 36.912 0.192 36.936 ;
    END
  END o_data[119]
  PIN o_data[11]
    DIRECTION OUTPUT ;
    USE SIGNAL ;
    PORT
      LAYER M4 ;
        RECT  0 9.936 0.192 9.96 ;
    END
  END o_data[11]
  PIN o_data[120]
    DIRECTION OUTPUT ;
    USE SIGNAL ;
    PORT
      LAYER M4 ;
        RECT  0 37.104 0.192 37.128 ;
    END
  END o_data[120]
  PIN o_data[121]
    DIRECTION OUTPUT ;
    USE SIGNAL ;
    PORT
      LAYER M4 ;
        RECT  0 37.392 0.192 37.416 ;
    END
  END o_data[121]
  PIN o_data[122]
    DIRECTION OUTPUT ;
    USE SIGNAL ;
    PORT
      LAYER M4 ;
        RECT  0 37.584 0.192 37.608 ;
    END
  END o_data[122]
  PIN o_data[123]
    DIRECTION OUTPUT ;
    USE SIGNAL ;
    PORT
      LAYER M4 ;
        RECT  0 37.872 0.192 37.896 ;
    END
  END o_data[123]
  PIN o_data[124]
    DIRECTION OUTPUT ;
    USE SIGNAL ;
    PORT
      LAYER M4 ;
        RECT  0 38.16 0.192 38.184 ;
    END
  END o_data[124]
  PIN o_data[125]
    DIRECTION OUTPUT ;
    USE SIGNAL ;
    PORT
      LAYER M4 ;
        RECT  0 38.352 0.192 38.376 ;
    END
  END o_data[125]
  PIN o_data[126]
    DIRECTION OUTPUT ;
    USE SIGNAL ;
    PORT
      LAYER M4 ;
        RECT  0 38.64 0.192 38.664 ;
    END
  END o_data[126]
  PIN o_data[127]
    DIRECTION OUTPUT ;
    USE SIGNAL ;
    PORT
      LAYER M4 ;
        RECT  0 38.832 0.192 38.856 ;
    END
  END o_data[127]
  PIN o_data[12]
    DIRECTION OUTPUT ;
    USE SIGNAL ;
    PORT
      LAYER M4 ;
        RECT  0 10.224 0.192 10.248 ;
    END
  END o_data[12]
  PIN o_data[13]
    DIRECTION OUTPUT ;
    USE SIGNAL ;
    PORT
      LAYER M4 ;
        RECT  0 10.416 0.192 10.44 ;
    END
  END o_data[13]
  PIN o_data[14]
    DIRECTION OUTPUT ;
    USE SIGNAL ;
    PORT
      LAYER M4 ;
        RECT  0 10.704 0.192 10.728 ;
    END
  END o_data[14]
  PIN o_data[15]
    DIRECTION OUTPUT ;
    USE SIGNAL ;
    PORT
      LAYER M4 ;
        RECT  0 10.992 0.192 11.016 ;
    END
  END o_data[15]
  PIN o_data[16]
    DIRECTION OUTPUT ;
    USE SIGNAL ;
    PORT
      LAYER M4 ;
        RECT  0 11.184 0.192 11.208 ;
    END
  END o_data[16]
  PIN o_data[17]
    DIRECTION OUTPUT ;
    USE SIGNAL ;
    PORT
      LAYER M4 ;
        RECT  0 11.472 0.192 11.496 ;
    END
  END o_data[17]
  PIN o_data[18]
    DIRECTION OUTPUT ;
    USE SIGNAL ;
    PORT
      LAYER M4 ;
        RECT  0 11.664 0.192 11.688 ;
    END
  END o_data[18]
  PIN o_data[19]
    DIRECTION OUTPUT ;
    USE SIGNAL ;
    PORT
      LAYER M4 ;
        RECT  0 11.952 0.192 11.976 ;
    END
  END o_data[19]
  PIN o_data[1]
    DIRECTION OUTPUT ;
    USE SIGNAL ;
    PORT
      LAYER M4 ;
        RECT  0 7.44 0.192 7.464 ;
    END
  END o_data[1]
  PIN o_data[20]
    DIRECTION OUTPUT ;
    USE SIGNAL ;
    PORT
      LAYER M4 ;
        RECT  0 12.24 0.192 12.264 ;
    END
  END o_data[20]
  PIN o_data[21]
    DIRECTION OUTPUT ;
    USE SIGNAL ;
    PORT
      LAYER M4 ;
        RECT  0 12.432 0.192 12.456 ;
    END
  END o_data[21]
  PIN o_data[22]
    DIRECTION OUTPUT ;
    USE SIGNAL ;
    PORT
      LAYER M4 ;
        RECT  0 12.72 0.192 12.744 ;
    END
  END o_data[22]
  PIN o_data[23]
    DIRECTION OUTPUT ;
    USE SIGNAL ;
    PORT
      LAYER M4 ;
        RECT  0 12.912 0.192 12.936 ;
    END
  END o_data[23]
  PIN o_data[24]
    DIRECTION OUTPUT ;
    USE SIGNAL ;
    PORT
      LAYER M4 ;
        RECT  0 13.2 0.192 13.224 ;
    END
  END o_data[24]
  PIN o_data[25]
    DIRECTION OUTPUT ;
    USE SIGNAL ;
    PORT
      LAYER M4 ;
        RECT  0 13.488 0.192 13.512 ;
    END
  END o_data[25]
  PIN o_data[26]
    DIRECTION OUTPUT ;
    USE SIGNAL ;
    PORT
      LAYER M4 ;
        RECT  0 13.68 0.192 13.704 ;
    END
  END o_data[26]
  PIN o_data[27]
    DIRECTION OUTPUT ;
    USE SIGNAL ;
    PORT
      LAYER M4 ;
        RECT  0 13.968 0.192 13.992 ;
    END
  END o_data[27]
  PIN o_data[28]
    DIRECTION OUTPUT ;
    USE SIGNAL ;
    PORT
      LAYER M4 ;
        RECT  0 14.16 0.192 14.184 ;
    END
  END o_data[28]
  PIN o_data[29]
    DIRECTION OUTPUT ;
    USE SIGNAL ;
    PORT
      LAYER M4 ;
        RECT  0 14.448 0.192 14.472 ;
    END
  END o_data[29]
  PIN o_data[2]
    DIRECTION OUTPUT ;
    USE SIGNAL ;
    PORT
      LAYER M4 ;
        RECT  0 7.728 0.192 7.752 ;
    END
  END o_data[2]
  PIN o_data[30]
    DIRECTION OUTPUT ;
    USE SIGNAL ;
    PORT
      LAYER M4 ;
        RECT  0 14.736 0.192 14.76 ;
    END
  END o_data[30]
  PIN o_data[31]
    DIRECTION OUTPUT ;
    USE SIGNAL ;
    PORT
      LAYER M4 ;
        RECT  0 14.928 0.192 14.952 ;
    END
  END o_data[31]
  PIN o_data[32]
    DIRECTION OUTPUT ;
    USE SIGNAL ;
    PORT
      LAYER M4 ;
        RECT  0 15.216 0.192 15.24 ;
    END
  END o_data[32]
  PIN o_data[33]
    DIRECTION OUTPUT ;
    USE SIGNAL ;
    PORT
      LAYER M4 ;
        RECT  0 15.408 0.192 15.432 ;
    END
  END o_data[33]
  PIN o_data[34]
    DIRECTION OUTPUT ;
    USE SIGNAL ;
    PORT
      LAYER M4 ;
        RECT  0 15.696 0.192 15.72 ;
    END
  END o_data[34]
  PIN o_data[35]
    DIRECTION OUTPUT ;
    USE SIGNAL ;
    PORT
      LAYER M4 ;
        RECT  0 15.984 0.192 16.008 ;
    END
  END o_data[35]
  PIN o_data[36]
    DIRECTION OUTPUT ;
    USE SIGNAL ;
    PORT
      LAYER M4 ;
        RECT  0 16.176 0.192 16.2 ;
    END
  END o_data[36]
  PIN o_data[37]
    DIRECTION OUTPUT ;
    USE SIGNAL ;
    PORT
      LAYER M4 ;
        RECT  0 16.464 0.192 16.488 ;
    END
  END o_data[37]
  PIN o_data[38]
    DIRECTION OUTPUT ;
    USE SIGNAL ;
    PORT
      LAYER M4 ;
        RECT  0 16.656 0.192 16.68 ;
    END
  END o_data[38]
  PIN o_data[39]
    DIRECTION OUTPUT ;
    USE SIGNAL ;
    PORT
      LAYER M4 ;
        RECT  0 16.944 0.192 16.968 ;
    END
  END o_data[39]
  PIN o_data[3]
    DIRECTION OUTPUT ;
    USE SIGNAL ;
    PORT
      LAYER M4 ;
        RECT  0 8.016 0.192 8.04 ;
    END
  END o_data[3]
  PIN o_data[40]
    DIRECTION OUTPUT ;
    USE SIGNAL ;
    PORT
      LAYER M4 ;
        RECT  0 17.232 0.192 17.256 ;
    END
  END o_data[40]
  PIN o_data[41]
    DIRECTION OUTPUT ;
    USE SIGNAL ;
    PORT
      LAYER M4 ;
        RECT  0 17.424 0.192 17.448 ;
    END
  END o_data[41]
  PIN o_data[42]
    DIRECTION OUTPUT ;
    USE SIGNAL ;
    PORT
      LAYER M4 ;
        RECT  0 17.712 0.192 17.736 ;
    END
  END o_data[42]
  PIN o_data[43]
    DIRECTION OUTPUT ;
    USE SIGNAL ;
    PORT
      LAYER M4 ;
        RECT  0 17.904 0.192 17.928 ;
    END
  END o_data[43]
  PIN o_data[44]
    DIRECTION OUTPUT ;
    USE SIGNAL ;
    PORT
      LAYER M4 ;
        RECT  0 18.192 0.192 18.216 ;
    END
  END o_data[44]
  PIN o_data[45]
    DIRECTION OUTPUT ;
    USE SIGNAL ;
    PORT
      LAYER M4 ;
        RECT  0 18.48 0.192 18.504 ;
    END
  END o_data[45]
  PIN o_data[46]
    DIRECTION OUTPUT ;
    USE SIGNAL ;
    PORT
      LAYER M4 ;
        RECT  0 18.672 0.192 18.696 ;
    END
  END o_data[46]
  PIN o_data[47]
    DIRECTION OUTPUT ;
    USE SIGNAL ;
    PORT
      LAYER M4 ;
        RECT  0 18.96 0.192 18.984 ;
    END
  END o_data[47]
  PIN o_data[48]
    DIRECTION OUTPUT ;
    USE SIGNAL ;
    PORT
      LAYER M4 ;
        RECT  0 19.152 0.192 19.176 ;
    END
  END o_data[48]
  PIN o_data[49]
    DIRECTION OUTPUT ;
    USE SIGNAL ;
    PORT
      LAYER M4 ;
        RECT  0 19.44 0.192 19.464 ;
    END
  END o_data[49]
  PIN o_data[4]
    DIRECTION OUTPUT ;
    USE SIGNAL ;
    PORT
      LAYER M4 ;
        RECT  0 8.208 0.192 8.232 ;
    END
  END o_data[4]
  PIN o_data[50]
    DIRECTION OUTPUT ;
    USE SIGNAL ;
    PORT
      LAYER M4 ;
        RECT  0 19.728 0.192 19.752 ;
    END
  END o_data[50]
  PIN o_data[51]
    DIRECTION OUTPUT ;
    USE SIGNAL ;
    PORT
      LAYER M4 ;
        RECT  0 19.92 0.192 19.944 ;
    END
  END o_data[51]
  PIN o_data[52]
    DIRECTION OUTPUT ;
    USE SIGNAL ;
    PORT
      LAYER M4 ;
        RECT  0 20.208 0.192 20.232 ;
    END
  END o_data[52]
  PIN o_data[53]
    DIRECTION OUTPUT ;
    USE SIGNAL ;
    PORT
      LAYER M4 ;
        RECT  0 20.4 0.192 20.424 ;
    END
  END o_data[53]
  PIN o_data[54]
    DIRECTION OUTPUT ;
    USE SIGNAL ;
    PORT
      LAYER M4 ;
        RECT  0 20.688 0.192 20.712 ;
    END
  END o_data[54]
  PIN o_data[55]
    DIRECTION OUTPUT ;
    USE SIGNAL ;
    PORT
      LAYER M4 ;
        RECT  0 20.976 0.192 21 ;
    END
  END o_data[55]
  PIN o_data[56]
    DIRECTION OUTPUT ;
    USE SIGNAL ;
    PORT
      LAYER M4 ;
        RECT  0 21.168 0.192 21.192 ;
    END
  END o_data[56]
  PIN o_data[57]
    DIRECTION OUTPUT ;
    USE SIGNAL ;
    PORT
      LAYER M4 ;
        RECT  0 21.456 0.192 21.48 ;
    END
  END o_data[57]
  PIN o_data[58]
    DIRECTION OUTPUT ;
    USE SIGNAL ;
    PORT
      LAYER M4 ;
        RECT  0 21.648 0.192 21.672 ;
    END
  END o_data[58]
  PIN o_data[59]
    DIRECTION OUTPUT ;
    USE SIGNAL ;
    PORT
      LAYER M4 ;
        RECT  0 21.936 0.192 21.96 ;
    END
  END o_data[59]
  PIN o_data[5]
    DIRECTION OUTPUT ;
    USE SIGNAL ;
    PORT
      LAYER M4 ;
        RECT  0 8.496 0.192 8.52 ;
    END
  END o_data[5]
  PIN o_data[60]
    DIRECTION OUTPUT ;
    USE SIGNAL ;
    PORT
      LAYER M4 ;
        RECT  0 22.128 0.192 22.152 ;
    END
  END o_data[60]
  PIN o_data[61]
    DIRECTION OUTPUT ;
    USE SIGNAL ;
    PORT
      LAYER M4 ;
        RECT  0 22.416 0.192 22.44 ;
    END
  END o_data[61]
  PIN o_data[62]
    DIRECTION OUTPUT ;
    USE SIGNAL ;
    PORT
      LAYER M4 ;
        RECT  0 22.704 0.192 22.728 ;
    END
  END o_data[62]
  PIN o_data[63]
    DIRECTION OUTPUT ;
    USE SIGNAL ;
    PORT
      LAYER M4 ;
        RECT  0 22.896 0.192 22.92 ;
    END
  END o_data[63]
  PIN o_data[64]
    DIRECTION OUTPUT ;
    USE SIGNAL ;
    PORT
      LAYER M4 ;
        RECT  0 23.184 0.192 23.208 ;
    END
  END o_data[64]
  PIN o_data[65]
    DIRECTION OUTPUT ;
    USE SIGNAL ;
    PORT
      LAYER M4 ;
        RECT  0 23.376 0.192 23.4 ;
    END
  END o_data[65]
  PIN o_data[66]
    DIRECTION OUTPUT ;
    USE SIGNAL ;
    PORT
      LAYER M4 ;
        RECT  0 23.664 0.192 23.688 ;
    END
  END o_data[66]
  PIN o_data[67]
    DIRECTION OUTPUT ;
    USE SIGNAL ;
    PORT
      LAYER M4 ;
        RECT  0 23.952 0.192 23.976 ;
    END
  END o_data[67]
  PIN o_data[68]
    DIRECTION OUTPUT ;
    USE SIGNAL ;
    PORT
      LAYER M4 ;
        RECT  0 24.144 0.192 24.168 ;
    END
  END o_data[68]
  PIN o_data[69]
    DIRECTION OUTPUT ;
    USE SIGNAL ;
    PORT
      LAYER M4 ;
        RECT  0 24.432 0.192 24.456 ;
    END
  END o_data[69]
  PIN o_data[6]
    DIRECTION OUTPUT ;
    USE SIGNAL ;
    PORT
      LAYER M4 ;
        RECT  0 8.688 0.192 8.712 ;
    END
  END o_data[6]
  PIN o_data[70]
    DIRECTION OUTPUT ;
    USE SIGNAL ;
    PORT
      LAYER M4 ;
        RECT  0 24.624 0.192 24.648 ;
    END
  END o_data[70]
  PIN o_data[71]
    DIRECTION OUTPUT ;
    USE SIGNAL ;
    PORT
      LAYER M4 ;
        RECT  0 24.912 0.192 24.936 ;
    END
  END o_data[71]
  PIN o_data[72]
    DIRECTION OUTPUT ;
    USE SIGNAL ;
    PORT
      LAYER M4 ;
        RECT  0 25.2 0.192 25.224 ;
    END
  END o_data[72]
  PIN o_data[73]
    DIRECTION OUTPUT ;
    USE SIGNAL ;
    PORT
      LAYER M4 ;
        RECT  0 25.392 0.192 25.416 ;
    END
  END o_data[73]
  PIN o_data[74]
    DIRECTION OUTPUT ;
    USE SIGNAL ;
    PORT
      LAYER M4 ;
        RECT  0 25.68 0.192 25.704 ;
    END
  END o_data[74]
  PIN o_data[75]
    DIRECTION OUTPUT ;
    USE SIGNAL ;
    PORT
      LAYER M4 ;
        RECT  0 25.872 0.192 25.896 ;
    END
  END o_data[75]
  PIN o_data[76]
    DIRECTION OUTPUT ;
    USE SIGNAL ;
    PORT
      LAYER M4 ;
        RECT  0 26.16 0.192 26.184 ;
    END
  END o_data[76]
  PIN o_data[77]
    DIRECTION OUTPUT ;
    USE SIGNAL ;
    PORT
      LAYER M4 ;
        RECT  0 26.448 0.192 26.472 ;
    END
  END o_data[77]
  PIN o_data[78]
    DIRECTION OUTPUT ;
    USE SIGNAL ;
    PORT
      LAYER M4 ;
        RECT  0 26.64 0.192 26.664 ;
    END
  END o_data[78]
  PIN o_data[79]
    DIRECTION OUTPUT ;
    USE SIGNAL ;
    PORT
      LAYER M4 ;
        RECT  0 26.928 0.192 26.952 ;
    END
  END o_data[79]
  PIN o_data[7]
    DIRECTION OUTPUT ;
    USE SIGNAL ;
    PORT
      LAYER M4 ;
        RECT  0 8.976 0.192 9 ;
    END
  END o_data[7]
  PIN o_data[80]
    DIRECTION OUTPUT ;
    USE SIGNAL ;
    PORT
      LAYER M4 ;
        RECT  0 27.12 0.192 27.144 ;
    END
  END o_data[80]
  PIN o_data[81]
    DIRECTION OUTPUT ;
    USE SIGNAL ;
    PORT
      LAYER M4 ;
        RECT  0 27.408 0.192 27.432 ;
    END
  END o_data[81]
  PIN o_data[82]
    DIRECTION OUTPUT ;
    USE SIGNAL ;
    PORT
      LAYER M4 ;
        RECT  0 27.696 0.192 27.72 ;
    END
  END o_data[82]
  PIN o_data[83]
    DIRECTION OUTPUT ;
    USE SIGNAL ;
    PORT
      LAYER M4 ;
        RECT  0 27.888 0.192 27.912 ;
    END
  END o_data[83]
  PIN o_data[84]
    DIRECTION OUTPUT ;
    USE SIGNAL ;
    PORT
      LAYER M4 ;
        RECT  0 28.176 0.192 28.2 ;
    END
  END o_data[84]
  PIN o_data[85]
    DIRECTION OUTPUT ;
    USE SIGNAL ;
    PORT
      LAYER M4 ;
        RECT  0 28.368 0.192 28.392 ;
    END
  END o_data[85]
  PIN o_data[86]
    DIRECTION OUTPUT ;
    USE SIGNAL ;
    PORT
      LAYER M4 ;
        RECT  0 28.656 0.192 28.68 ;
    END
  END o_data[86]
  PIN o_data[87]
    DIRECTION OUTPUT ;
    USE SIGNAL ;
    PORT
      LAYER M4 ;
        RECT  0 28.944 0.192 28.968 ;
    END
  END o_data[87]
  PIN o_data[88]
    DIRECTION OUTPUT ;
    USE SIGNAL ;
    PORT
      LAYER M4 ;
        RECT  0 29.136 0.192 29.16 ;
    END
  END o_data[88]
  PIN o_data[89]
    DIRECTION OUTPUT ;
    USE SIGNAL ;
    PORT
      LAYER M4 ;
        RECT  0 29.424 0.192 29.448 ;
    END
  END o_data[89]
  PIN o_data[8]
    DIRECTION OUTPUT ;
    USE SIGNAL ;
    PORT
      LAYER M4 ;
        RECT  0 9.168 0.192 9.192 ;
    END
  END o_data[8]
  PIN o_data[90]
    DIRECTION OUTPUT ;
    USE SIGNAL ;
    PORT
      LAYER M4 ;
        RECT  0 29.616 0.192 29.64 ;
    END
  END o_data[90]
  PIN o_data[91]
    DIRECTION OUTPUT ;
    USE SIGNAL ;
    PORT
      LAYER M4 ;
        RECT  0 29.904 0.192 29.928 ;
    END
  END o_data[91]
  PIN o_data[92]
    DIRECTION OUTPUT ;
    USE SIGNAL ;
    PORT
      LAYER M4 ;
        RECT  0 30.192 0.192 30.216 ;
    END
  END o_data[92]
  PIN o_data[93]
    DIRECTION OUTPUT ;
    USE SIGNAL ;
    PORT
      LAYER M4 ;
        RECT  0 30.384 0.192 30.408 ;
    END
  END o_data[93]
  PIN o_data[94]
    DIRECTION OUTPUT ;
    USE SIGNAL ;
    PORT
      LAYER M4 ;
        RECT  0 30.672 0.192 30.696 ;
    END
  END o_data[94]
  PIN o_data[95]
    DIRECTION OUTPUT ;
    USE SIGNAL ;
    PORT
      LAYER M4 ;
        RECT  0 30.864 0.192 30.888 ;
    END
  END o_data[95]
  PIN o_data[96]
    DIRECTION OUTPUT ;
    USE SIGNAL ;
    PORT
      LAYER M4 ;
        RECT  0 31.152 0.192 31.176 ;
    END
  END o_data[96]
  PIN o_data[97]
    DIRECTION OUTPUT ;
    USE SIGNAL ;
    PORT
      LAYER M4 ;
        RECT  0 31.44 0.192 31.464 ;
    END
  END o_data[97]
  PIN o_data[98]
    DIRECTION OUTPUT ;
    USE SIGNAL ;
    PORT
      LAYER M4 ;
        RECT  0 31.632 0.192 31.656 ;
    END
  END o_data[98]
  PIN o_data[99]
    DIRECTION OUTPUT ;
    USE SIGNAL ;
    PORT
      LAYER M4 ;
        RECT  0 31.92 0.192 31.944 ;
    END
  END o_data[99]
  PIN o_data[9]
    DIRECTION OUTPUT ;
    USE SIGNAL ;
    PORT
      LAYER M4 ;
        RECT  0 9.456 0.192 9.48 ;
    END
  END o_data[9]
  PIN o_mask[0]
    DIRECTION OUTPUT ;
    USE SIGNAL ;
    PORT
      LAYER M4 ;
        RECT  0 6.192 0.192 6.216 ;
    END
  END o_mask[0]
  PIN o_mask[1]
    DIRECTION OUTPUT ;
    USE SIGNAL ;
    PORT
      LAYER M4 ;
        RECT  0 6.48 0.192 6.504 ;
    END
  END o_mask[1]
  PIN o_mask[2]
    DIRECTION OUTPUT ;
    USE SIGNAL ;
    PORT
      LAYER M4 ;
        RECT  0 6.768 0.192 6.792 ;
    END
  END o_mask[2]
  PIN o_mask[3]
    DIRECTION OUTPUT ;
    USE SIGNAL ;
    PORT
      LAYER M4 ;
        RECT  0 6.96 0.192 6.984 ;
    END
  END o_mask[3]
  PIN o_row[0]
    DIRECTION OUTPUT ;
    USE SIGNAL ;
    PORT
      LAYER M4 ;
        RECT  0 2.736 0.192 2.76 ;
    END
  END o_row[0]
  PIN o_row[10]
    DIRECTION OUTPUT ;
    USE SIGNAL ;
    PORT
      LAYER M4 ;
        RECT  0 5.232 0.192 5.256 ;
    END
  END o_row[10]
  PIN o_row[11]
    DIRECTION OUTPUT ;
    USE SIGNAL ;
    PORT
      LAYER M4 ;
        RECT  0 5.52 0.192 5.544 ;
    END
  END o_row[11]
  PIN o_row[12]
    DIRECTION OUTPUT ;
    USE SIGNAL ;
    PORT
      LAYER M4 ;
        RECT  0 5.712 0.192 5.736 ;
    END
  END o_row[12]
  PIN o_row[13]
    DIRECTION OUTPUT ;
    USE SIGNAL ;
    PORT
      LAYER M4 ;
        RECT  0 6 0.192 6.024 ;
    END
  END o_row[13]
  PIN o_row[1]
    DIRECTION OUTPUT ;
    USE SIGNAL ;
    PORT
      LAYER M4 ;
        RECT  0 3.024 0.192 3.048 ;
    END
  END o_row[1]
  PIN o_row[2]
    DIRECTION OUTPUT ;
    USE SIGNAL ;
    PORT
      LAYER M4 ;
        RECT  0 3.216 0.192 3.24 ;
    END
  END o_row[2]
  PIN o_row[3]
    DIRECTION OUTPUT ;
    USE SIGNAL ;
    PORT
      LAYER M4 ;
        RECT  0 3.504 0.192 3.528 ;
    END
  END o_row[3]
  PIN o_row[4]
    DIRECTION OUTPUT ;
    USE SIGNAL ;
    PORT
      LAYER M4 ;
        RECT  0 3.696 0.192 3.72 ;
    END
  END o_row[4]
  PIN o_row[5]
    DIRECTION OUTPUT ;
    USE SIGNAL ;
    PORT
      LAYER M4 ;
        RECT  0 3.984 0.192 4.008 ;
    END
  END o_row[5]
  PIN o_row[6]
    DIRECTION OUTPUT ;
    USE SIGNAL ;
    PORT
      LAYER M4 ;
        RECT  0 4.272 0.192 4.296 ;
    END
  END o_row[6]
  PIN o_row[7]
    DIRECTION OUTPUT ;
    USE SIGNAL ;
    PORT
      LAYER M4 ;
        RECT  0 4.464 0.192 4.488 ;
    END
  END o_row[7]
  PIN o_row[8]
    DIRECTION OUTPUT ;
    USE SIGNAL ;
    PORT
      LAYER M4 ;
        RECT  0 4.752 0.192 4.776 ;
    END
  END o_row[8]
  PIN o_row[9]
    DIRECTION OUTPUT ;
    USE SIGNAL ;
    PORT
      LAYER M4 ;
        RECT  0 4.944 0.192 4.968 ;
    END
  END o_row[9]
  PIN o_tag[0]
    DIRECTION OUTPUT ;
    USE SIGNAL ;
    PORT
      LAYER M4 ;
        RECT  0 39.12 0.192 39.144 ;
    END
  END o_tag[0]
  PIN o_tag[1]
    DIRECTION OUTPUT ;
    USE SIGNAL ;
    PORT
      LAYER M4 ;
        RECT  0 39.408 0.192 39.432 ;
    END
  END o_tag[1]
  PIN o_tag[2]
    DIRECTION OUTPUT ;
    USE SIGNAL ;
    PORT
      LAYER M4 ;
        RECT  0 39.6 0.192 39.624 ;
    END
  END o_tag[2]
  PIN o_tag[3]
    DIRECTION OUTPUT ;
    USE SIGNAL ;
    PORT
      LAYER M4 ;
        RECT  0 39.888 0.192 39.912 ;
    END
  END o_tag[3]
  PIN o_tag[4]
    DIRECTION OUTPUT ;
    USE SIGNAL ;
    PORT
      LAYER M4 ;
        RECT  0 40.08 0.192 40.104 ;
    END
  END o_tag[4]
  PIN o_tag[5]
    DIRECTION OUTPUT ;
    USE SIGNAL ;
    PORT
      LAYER M4 ;
        RECT  0 40.368 0.192 40.392 ;
    END
  END o_tag[5]
  PIN o_tag[6]
    DIRECTION OUTPUT ;
    USE SIGNAL ;
    PORT
      LAYER M4 ;
        RECT  0 40.656 0.192 40.68 ;
    END
  END o_tag[6]
  PIN o_tag[7]
    DIRECTION OUTPUT ;
    USE SIGNAL ;
    PORT
      LAYER M4 ;
        RECT  0 40.848 0.192 40.872 ;
    END
  END o_tag[7]
  PIN o_v
    DIRECTION OUTPUT ;
    USE SIGNAL ;
    PORT
      LAYER M4 ;
        RECT  0 2.256 0.192 2.28 ;
    END
  END o_v
  PIN o_we
    DIRECTION OUTPUT ;
    USE SIGNAL ;
    PORT
      LAYER M4 ;
        RECT  0 2.448 0.192 2.472 ;
    END
  END o_we
  PIN rst_n
    DIRECTION INPUT ;
    USE SIGNAL ;
    PORT
      LAYER M4 ;
        RECT  43.008 22.032 43.2 22.056 ;
    END
  END rst_n
  PIN VDD
    DIRECTION INOUT ;
    USE POWER ;
    PORT
      LAYER M5 ;
        RECT  40.392 2.151 40.512 41.049 ;
        RECT  34.992 2.151 35.112 41.049 ;
        RECT  29.592 2.151 29.712 41.049 ;
        RECT  24.192 2.151 24.312 41.049 ;
        RECT  18.792 2.151 18.912 41.049 ;
        RECT  13.392 2.151 13.512 41.049 ;
        RECT  7.992 2.151 8.112 41.049 ;
        RECT  2.592 2.151 2.712 41.049 ;
    END
  END VDD
  PIN VSS
    DIRECTION INOUT ;
    USE GROUND ;
    PORT
      LAYER M5 ;
        RECT  40.2 2.137 40.32 41.063 ;
        RECT  34.8 2.137 34.92 41.063 ;
        RECT  29.4 2.137 29.52 41.063 ;
        RECT  24 2.137 24.12 41.063 ;
        RECT  18.6 2.137 18.72 41.063 ;
        RECT  13.2 2.137 13.32 41.063 ;
        RECT  7.8 2.137 7.92 41.063 ;
        RECT  2.4 2.137 2.52 41.063 ;
    END
  END VSS
  # OT_OBS_CLOSED layer=M5 d_um=1.536 added=22
  OBS
    LAYER RVTN ;
     RECT  2.16 2.16 41.04 2.295 ;
     RECT  2.16 2.565 41.04 2.835 ;
     RECT  2.16 3.105 41.04 3.375 ;
     RECT  2.16 3.645 41.04 3.915 ;
     RECT  2.16 4.185 41.04 4.455 ;
     RECT  2.16 4.725 41.04 4.995 ;
     RECT  2.16 5.265 41.04 5.535 ;
     RECT  2.16 5.805 41.04 6.075 ;
     RECT  2.16 6.345 41.04 6.615 ;
     RECT  2.16 6.885 41.04 7.155 ;
     RECT  2.16 7.425 41.04 7.695 ;
     RECT  2.16 7.965 41.04 8.235 ;
     RECT  2.16 8.505 41.04 8.775 ;
     RECT  2.16 9.045 41.04 9.315 ;
     RECT  2.16 9.585 41.04 9.855 ;
     RECT  2.16 10.125 41.04 10.395 ;
     RECT  2.16 10.665 41.04 10.935 ;
     RECT  2.16 11.205 41.04 11.475 ;
     RECT  2.16 11.745 41.04 12.015 ;
     RECT  2.16 12.285 41.04 12.555 ;
     RECT  2.16 12.825 41.04 13.095 ;
     RECT  2.16 13.365 41.04 13.635 ;
     RECT  2.16 13.905 41.04 14.175 ;
     RECT  2.16 14.445 41.04 14.715 ;
     RECT  2.16 14.985 41.04 15.255 ;
     RECT  2.16 15.525 41.04 15.795 ;
     RECT  2.16 16.065 41.04 16.335 ;
     RECT  2.16 16.605 41.04 16.875 ;
     RECT  2.16 17.145 41.04 17.415 ;
     RECT  2.16 17.685 41.04 17.955 ;
     RECT  2.16 18.225 41.04 18.495 ;
     RECT  2.16 18.765 41.04 19.035 ;
     RECT  2.16 19.305 41.04 19.575 ;
     RECT  2.16 19.845 41.04 20.115 ;
     RECT  2.16 20.385 41.04 20.655 ;
     RECT  2.16 20.925 41.04 21.195 ;
     RECT  2.16 21.465 41.04 21.735 ;
     RECT  2.16 22.005 41.04 22.275 ;
     RECT  2.16 22.545 41.04 22.815 ;
     RECT  2.16 23.085 41.04 23.355 ;
     RECT  2.16 23.625 41.04 23.895 ;
     RECT  2.16 24.165 41.04 24.435 ;
     RECT  2.16 24.705 41.04 24.975 ;
     RECT  2.16 25.245 41.04 25.515 ;
     RECT  2.16 25.785 41.04 26.055 ;
     RECT  2.16 26.325 41.04 26.595 ;
     RECT  2.16 26.865 41.04 27.135 ;
     RECT  2.16 27.405 41.04 27.675 ;
     RECT  2.16 27.945 41.04 28.215 ;
     RECT  2.16 28.485 41.04 28.755 ;
     RECT  2.16 29.025 41.04 29.295 ;
     RECT  2.16 29.565 41.04 29.835 ;
     RECT  2.16 30.105 41.04 30.375 ;
     RECT  2.16 30.645 41.04 30.915 ;
     RECT  2.16 31.185 41.04 31.455 ;
     RECT  2.16 31.725 41.04 31.995 ;
     RECT  2.16 32.265 41.04 32.535 ;
     RECT  2.16 32.805 41.04 33.075 ;
     RECT  2.16 33.345 41.04 33.615 ;
     RECT  2.16 33.885 41.04 34.155 ;
     RECT  2.16 34.425 41.04 34.695 ;
     RECT  2.16 34.965 41.04 35.235 ;
     RECT  2.16 35.505 41.04 35.775 ;
     RECT  2.16 36.045 41.04 36.315 ;
     RECT  2.16 36.585 41.04 36.855 ;
     RECT  2.16 37.125 41.04 37.395 ;
     RECT  2.16 37.665 41.04 37.935 ;
     RECT  2.16 38.205 41.04 38.475 ;
     RECT  2.16 38.745 41.04 39.015 ;
     RECT  2.16 39.285 41.04 39.555 ;
     RECT  2.16 39.825 41.04 40.095 ;
     RECT  2.16 40.365 41.04 40.635 ;
     RECT  2.16 40.905 41.04 41.04 ;
    LAYER RVTP ;
     RECT  2.16 2.295 41.04 2.565 ;
     RECT  2.16 2.835 41.04 3.105 ;
     RECT  2.16 3.375 41.04 3.645 ;
     RECT  2.16 3.915 41.04 4.185 ;
     RECT  2.16 4.455 41.04 4.725 ;
     RECT  2.16 4.995 41.04 5.265 ;
     RECT  2.16 5.535 41.04 5.805 ;
     RECT  2.16 6.075 41.04 6.345 ;
     RECT  2.16 6.615 41.04 6.885 ;
     RECT  2.16 7.155 41.04 7.425 ;
     RECT  2.16 7.695 41.04 7.965 ;
     RECT  2.16 8.235 41.04 8.505 ;
     RECT  2.16 8.775 41.04 9.045 ;
     RECT  2.16 9.315 41.04 9.585 ;
     RECT  2.16 9.855 41.04 10.125 ;
     RECT  2.16 10.395 41.04 10.665 ;
     RECT  2.16 10.935 41.04 11.205 ;
     RECT  2.16 11.475 41.04 11.745 ;
     RECT  2.16 12.015 41.04 12.285 ;
     RECT  2.16 12.555 41.04 12.825 ;
     RECT  2.16 13.095 41.04 13.365 ;
     RECT  2.16 13.635 41.04 13.905 ;
     RECT  2.16 14.175 41.04 14.445 ;
     RECT  2.16 14.715 41.04 14.985 ;
     RECT  2.16 15.255 41.04 15.525 ;
     RECT  2.16 15.795 41.04 16.065 ;
     RECT  2.16 16.335 41.04 16.605 ;
     RECT  2.16 16.875 41.04 17.145 ;
     RECT  2.16 17.415 41.04 17.685 ;
     RECT  2.16 17.955 41.04 18.225 ;
     RECT  2.16 18.495 41.04 18.765 ;
     RECT  2.16 19.035 41.04 19.305 ;
     RECT  2.16 19.575 41.04 19.845 ;
     RECT  2.16 20.115 41.04 20.385 ;
     RECT  2.16 20.655 41.04 20.925 ;
     RECT  2.16 21.195 41.04 21.465 ;
     RECT  2.16 21.735 41.04 22.005 ;
     RECT  2.16 22.275 41.04 22.545 ;
     RECT  2.16 22.815 41.04 23.085 ;
     RECT  2.16 23.355 41.04 23.625 ;
     RECT  2.16 23.895 41.04 24.165 ;
     RECT  2.16 24.435 41.04 24.705 ;
     RECT  2.16 24.975 41.04 25.245 ;
     RECT  2.16 25.515 41.04 25.785 ;
     RECT  2.16 26.055 41.04 26.325 ;
     RECT  2.16 26.595 41.04 26.865 ;
     RECT  2.16 27.135 41.04 27.405 ;
     RECT  2.16 27.675 41.04 27.945 ;
     RECT  2.16 28.215 41.04 28.485 ;
     RECT  2.16 28.755 41.04 29.025 ;
     RECT  2.16 29.295 41.04 29.565 ;
     RECT  2.16 29.835 41.04 30.105 ;
     RECT  2.16 30.375 41.04 30.645 ;
     RECT  2.16 30.915 41.04 31.185 ;
     RECT  2.16 31.455 41.04 31.725 ;
     RECT  2.16 31.995 41.04 32.265 ;
     RECT  2.16 32.535 41.04 32.805 ;
     RECT  2.16 33.075 41.04 33.345 ;
     RECT  2.16 33.615 41.04 33.885 ;
     RECT  2.16 34.155 41.04 34.425 ;
     RECT  2.16 34.695 41.04 34.965 ;
     RECT  2.16 35.235 41.04 35.505 ;
     RECT  2.16 35.775 41.04 36.045 ;
     RECT  2.16 36.315 41.04 36.585 ;
     RECT  2.16 36.855 41.04 37.125 ;
     RECT  2.16 37.395 41.04 37.665 ;
     RECT  2.16 37.935 41.04 38.205 ;
     RECT  2.16 38.475 41.04 38.745 ;
     RECT  2.16 39.015 41.04 39.285 ;
     RECT  2.16 39.555 41.04 39.825 ;
     RECT  2.16 40.095 41.04 40.365 ;
     RECT  2.16 40.635 41.04 40.905 ;
    LAYER M1 ;
     RECT  2.16 2.151 41.04 41.049 ;
    LAYER M2 ;
     RECT  0.211 12.366 0.499 13.014 ;
     RECT  0.499 11.826 0.535 13.014 ;
     RECT  0.499 36.666 0.535 36.684 ;
     RECT  0.247 38.106 0.535 38.124 ;
     RECT  0.211 39.294 0.535 39.816 ;
     RECT  0.211 7.326 2.16 8.532 ;
     RECT  0.535 11.214 2.16 13.662 ;
     RECT  0.535 16.884 2.16 17.514 ;
     RECT  0.211 21.546 2.16 21.564 ;
     RECT  0.211 22.716 2.16 22.734 ;
     RECT  0.211 24.48 2.16 24.498 ;
     RECT  0.211 27.216 2.16 27.234 ;
     RECT  0.211 30.726 2.16 30.744 ;
     RECT  0.211 31.896 2.16 31.914 ;
     RECT  0.535 36.324 2.16 36.684 ;
     RECT  0.535 38.106 2.16 39.816 ;
     RECT  2.16 2.151 41.04 41.049 ;
     RECT  41.04 22.212 41.063 22.23 ;
    LAYER M3 ;
     RECT  2.415 2.143 2.505 2.191 ;
     RECT  2.376 2.191 2.505 2.335 ;
     RECT  3.6 2.191 3.618 2.335 ;
     RECT  7.815 2.143 7.905 2.413 ;
     RECT  13.215 2.143 13.305 2.413 ;
     RECT  18.615 2.143 18.705 2.413 ;
     RECT  24.015 2.143 24.105 2.413 ;
     RECT  29.415 2.143 29.505 2.413 ;
     RECT  34.815 2.143 34.905 2.413 ;
     RECT  40.215 2.143 40.305 2.413 ;
     RECT  2.304 2.335 3.618 2.641 ;
     RECT  2.304 2.641 4.086 3.245 ;
     RECT  2.415 3.245 4.086 3.379 ;
     RECT  2.415 3.379 4.554 3.979 ;
     RECT  2.304 3.979 4.554 4.261 ;
     RECT  2.304 4.261 4.842 4.267 ;
     RECT  2.268 4.267 4.842 4.559 ;
     RECT  2.304 4.559 4.842 5.611 ;
     RECT  5.58 4.999 5.598 5.611 ;
     RECT  2.304 5.611 5.598 6.241 ;
     RECT  7.815 2.413 8.097 6.691 ;
     RECT  2.304 6.241 5.634 6.817 ;
     RECT  7.668 6.691 8.097 7.231 ;
     RECT  7.164 7.231 8.097 7.699 ;
     RECT  2.304 6.817 5.994 7.763 ;
     RECT  7.164 7.699 8.406 7.861 ;
     RECT  7.164 7.861 8.514 8.473 ;
     RECT  2.412 7.763 5.994 8.491 ;
     RECT  2.376 8.491 5.994 8.707 ;
     RECT  0.216 7.321 0.234 8.717 ;
     RECT  2.304 8.707 5.994 9.013 ;
     RECT  7.164 8.473 8.91 9.589 ;
     RECT  2.304 9.013 6.03 9.661 ;
     RECT  6.804 9.589 8.91 9.661 ;
     RECT  2.304 9.661 9.414 10.769 ;
     RECT  10.548 10.291 10.566 10.831 ;
     RECT  10.548 10.831 10.71 11.101 ;
     RECT  0.54 11.209 0.558 11.821 ;
     RECT  2.34 10.769 9.414 11.947 ;
     RECT  2.304 11.947 9.414 12.119 ;
     RECT  10.26 11.101 10.71 12.217 ;
     RECT  0.504 11.821 0.558 12.269 ;
     RECT  0.504 12.269 0.522 12.361 ;
     RECT  0.216 12.361 0.522 12.461 ;
     RECT  2.376 12.119 9.414 12.901 ;
     RECT  13.215 2.413 13.497 12.901 ;
     RECT  11.952 11.245 11.97 13.063 ;
     RECT  12.708 12.901 13.497 13.063 ;
     RECT  0.216 12.461 0.234 13.229 ;
     RECT  11.952 13.063 13.497 13.639 ;
     RECT  14.364 12.793 14.382 13.639 ;
     RECT  0.54 13.639 0.558 13.709 ;
     RECT  11.952 13.639 14.382 14.791 ;
     RECT  11.952 14.791 14.418 15.061 ;
     RECT  15.408 15.187 15.426 15.331 ;
     RECT  11.952 15.061 14.598 15.601 ;
     RECT  15.408 15.331 15.498 15.601 ;
     RECT  11.952 15.601 15.498 16.069 ;
     RECT  11.952 16.069 16.11 16.681 ;
     RECT  11.952 16.681 16.506 16.807 ;
     RECT  2.304 12.901 9.414 17.339 ;
     RECT  11.952 16.807 16.938 17.383 ;
     RECT  17.784 16.843 17.802 17.383 ;
     RECT  11.952 17.383 17.802 17.491 ;
     RECT  18.615 2.413 18.897 17.491 ;
     RECT  0.54 16.879 0.558 17.933 ;
     RECT  2.376 17.339 9.414 18.475 ;
     RECT  11.952 17.491 18.897 18.571 ;
     RECT  10.26 12.217 11.106 19.229 ;
     RECT  11.952 18.571 19.098 19.345 ;
     RECT  10.26 19.229 10.746 19.499 ;
     RECT  11.952 19.345 19.53 19.651 ;
     RECT  11.952 19.651 19.71 20.039 ;
     RECT  10.512 19.499 10.746 20.191 ;
     RECT  12.204 20.039 19.71 20.191 ;
     RECT  20.52 20.083 20.538 20.191 ;
     RECT  12.204 20.191 20.538 20.309 ;
     RECT  20.52 20.309 20.538 20.461 ;
     RECT  2.304 18.475 9.414 20.551 ;
     RECT  2.304 20.551 9.774 20.731 ;
     RECT  10.512 20.191 11.034 20.731 ;
     RECT  20.52 20.461 20.646 20.731 ;
     RECT  2.304 20.731 11.034 21.271 ;
     RECT  12.204 20.309 19.71 21.271 ;
     RECT  20.52 20.731 20.862 21.271 ;
     RECT  2.304 21.271 19.71 21.541 ;
     RECT  20.52 21.271 21.15 21.541 ;
     RECT  0.216 21.541 0.234 21.677 ;
     RECT  40.215 2.413 40.497 22.027 ;
     RECT  40.215 22.027 41.058 22.235 ;
     RECT  22.464 22.351 22.482 22.477 ;
     RECT  36.504 22.171 36.522 22.505 ;
     RECT  30.744 22.441 30.762 22.541 ;
     RECT  2.304 21.541 21.618 22.621 ;
     RECT  22.464 22.477 22.806 22.621 ;
     RECT  2.304 22.621 22.806 22.783 ;
     RECT  2.304 22.783 23.058 22.891 ;
     RECT  24.015 2.413 24.297 22.891 ;
     RECT  0.216 22.711 0.234 22.925 ;
     RECT  2.304 22.891 24.297 24.125 ;
     RECT  2.304 24.125 21.69 24.359 ;
     RECT  0.216 24.475 0.234 24.653 ;
     RECT  22.428 24.125 24.297 24.781 ;
     RECT  22.428 24.781 24.534 25.285 ;
     RECT  25.272 25.177 25.29 25.285 ;
     RECT  22.428 25.285 25.29 25.519 ;
     RECT  22.428 25.519 25.722 25.789 ;
     RECT  22.428 25.789 26.01 25.861 ;
     RECT  22.428 25.861 26.37 26.221 ;
     RECT  22.428 26.221 26.694 26.401 ;
     RECT  22.428 26.401 26.874 26.671 ;
     RECT  22.428 26.671 27.342 27.211 ;
     RECT  22.428 27.211 27.522 27.337 ;
     RECT  2.304 24.359 21.618 27.365 ;
     RECT  0.216 27.211 0.234 27.437 ;
     RECT  22.428 27.337 27.666 27.913 ;
     RECT  22.428 27.913 27.774 28.147 ;
     RECT  2.412 27.365 21.618 28.171 ;
     RECT  22.428 28.147 28.242 28.561 ;
     RECT  29.415 2.413 29.697 28.561 ;
     RECT  0.216 29.419 0.234 29.549 ;
     RECT  22.428 28.561 29.697 29.605 ;
     RECT  2.304 28.171 21.618 30.677 ;
     RECT  2.34 30.677 21.618 30.713 ;
     RECT  2.376 30.713 21.618 30.811 ;
     RECT  22.428 29.605 30.222 30.811 ;
     RECT  0.216 30.721 0.234 30.893 ;
     RECT  2.376 30.811 30.474 31.351 ;
     RECT  2.376 31.351 30.618 31.621 ;
     RECT  31.752 31.387 31.77 31.621 ;
     RECT  2.376 31.621 31.77 31.657 ;
     RECT  2.304 31.657 31.77 31.801 ;
     RECT  0.216 31.891 0.234 31.949 ;
     RECT  2.304 31.801 32.382 32.701 ;
     RECT  2.304 32.701 32.526 32.875 ;
     RECT  2.268 32.875 32.526 32.971 ;
     RECT  2.268 32.971 32.706 33.107 ;
     RECT  34.815 2.413 35.097 33.781 ;
     RECT  2.304 33.107 32.706 33.809 ;
     RECT  22.428 33.809 32.706 33.817 ;
     RECT  2.304 33.809 21.618 34.735 ;
     RECT  22.428 33.817 33.354 34.735 ;
     RECT  34.38 33.781 35.097 34.861 ;
     RECT  34.38 34.861 35.19 35.401 ;
     RECT  0.216 35.515 0.234 35.693 ;
     RECT  2.304 34.735 33.354 35.707 ;
     RECT  34.38 35.401 35.226 35.707 ;
     RECT  0.54 36.319 0.558 36.661 ;
     RECT  2.304 35.707 35.226 36.751 ;
     RECT  36.144 35.671 36.162 36.751 ;
     RECT  0.504 36.661 0.558 36.941 ;
     RECT  2.304 36.751 36.162 37.049 ;
     RECT  0.504 36.941 0.522 37.133 ;
     RECT  37.476 37.435 37.494 37.471 ;
     RECT  2.376 37.049 36.162 37.669 ;
     RECT  2.376 37.669 36.342 37.705 ;
     RECT  2.376 37.705 36.702 37.867 ;
     RECT  40.215 22.235 40.497 38.011 ;
     RECT  37.476 37.471 37.602 38.101 ;
     RECT  40.215 38.011 40.914 38.107 ;
     RECT  37.476 38.101 37.782 38.173 ;
     RECT  2.304 37.867 36.702 38.209 ;
     RECT  37.44 38.173 37.782 38.209 ;
     RECT  39.924 38.107 40.914 38.281 ;
     RECT  0.252 38.101 0.27 38.347 ;
     RECT  2.304 38.209 37.782 38.371 ;
     RECT  38.52 37.741 38.538 38.371 ;
     RECT  39.816 38.281 40.914 38.371 ;
     RECT  2.304 38.371 40.914 38.399 ;
     RECT  0.216 38.347 0.27 38.477 ;
     RECT  0.252 38.477 0.27 38.551 ;
     RECT  0.252 38.551 0.558 39.149 ;
     RECT  2.304 38.399 40.734 39.865 ;
     RECT  0.216 39.289 0.234 39.917 ;
     RECT  2.268 39.865 40.734 40.493 ;
     RECT  2.304 40.493 40.734 40.711 ;
     RECT  2.304 40.711 40.914 40.733 ;
     RECT  2.304 40.733 10.998 40.829 ;
     RECT  11.844 40.733 40.914 40.829 ;
     RECT  3.384 40.829 3.438 40.865 ;
     RECT  2.304 40.829 2.646 40.877 ;
     RECT  3.384 40.865 3.402 41.021 ;
     RECT  4.536 40.829 10.962 41.021 ;
     RECT  11.844 40.829 15.642 41.021 ;
     RECT  16.884 40.829 21.258 41.021 ;
     RECT  22.32 40.829 37.566 41.021 ;
     RECT  38.304 40.829 40.698 41.021 ;
     RECT  2.415 40.877 2.646 41.057 ;
     RECT  34.416 41.021 34.905 41.057 ;
     RECT  2.556 41.057 2.646 41.165 ;
     RECT  18.216 41.021 18.99 41.165 ;
     RECT  2.556 41.165 2.574 41.213 ;
     RECT  7.668 41.021 9.126 41.213 ;
     RECT  13.176 41.021 13.662 41.213 ;
     RECT  18.216 41.165 18.774 41.213 ;
     RECT  29.376 41.021 29.646 41.213 ;
     RECT  7.704 41.213 9.126 41.645 ;
     RECT  10.188 41.021 10.242 41.645 ;
     RECT  15.624 41.021 15.642 41.645 ;
     RECT  26.208 41.021 26.766 41.645 ;
     RECT  34.416 41.057 34.434 41.645 ;
     RECT  37.26 41.021 37.278 41.645 ;
     RECT  38.304 41.021 38.754 41.645 ;
     RECT  7.704 41.645 8.514 42.221 ;
     RECT  10.224 41.645 10.242 42.221 ;
     RECT  13.644 41.213 13.662 42.221 ;
     RECT  14.724 41.021 14.742 42.221 ;
     RECT  18.216 41.213 18.234 42.221 ;
     RECT  23.832 41.021 24.498 42.221 ;
     RECT  26.748 41.645 26.766 42.221 ;
     RECT  29.628 41.213 29.646 42.221 ;
     RECT  30.636 41.021 30.654 42.221 ;
     RECT  38.304 41.645 38.322 42.221 ;
     RECT  39.708 41.021 40.446 42.221 ;
     RECT  7.704 42.221 7.722 42.269 ;
    LAYER M4 ;
     RECT  0.156 2.256 2.408 40.872 ;
     RECT  2.408 2.148 2.437 41.052 ;
     RECT  2.437 2.148 2.512 41.208 ;
     RECT  2.512 2.418 2.589 41.208 ;
     RECT  2.589 2.418 2.675 41.16 ;
     RECT  2.675 2.418 2.704 41.016 ;
     RECT  2.704 8.208 2.729 8.232 ;
     RECT  2.704 14.448 2.729 15.24 ;
     RECT  2.704 20.4 2.729 21.48 ;
     RECT  2.704 4.464 2.765 4.488 ;
     RECT  2.704 22.752 2.765 23.976 ;
     RECT  2.704 34.128 2.765 34.152 ;
     RECT  2.704 5.52 2.837 5.544 ;
     RECT  2.729 15.216 2.837 15.24 ;
     RECT  2.704 16.848 2.981 16.872 ;
     RECT  2.729 20.4 3.161 21 ;
     RECT  2.704 29.52 3.161 29.544 ;
     RECT  2.704 26.784 3.197 26.952 ;
     RECT  3.161 20.976 3.413 21 ;
     RECT  2.704 36.624 3.413 41.016 ;
     RECT  2.704 25.152 3.449 25.176 ;
     RECT  3.805 21.552 3.917 21.576 ;
     RECT  3.925 28.464 4.012 28.488 ;
     RECT  2.704 35.52 4.025 35.544 ;
     RECT  2.765 22.752 4.061 22.776 ;
     RECT  2.704 18.672 4.277 18.696 ;
     RECT  4.268 16.176 4.355 16.2 ;
     RECT  3.413 36.624 4.453 40.632 ;
     RECT  4.345 14.832 4.493 14.856 ;
     RECT  3.197 26.928 4.493 26.952 ;
     RECT  4.453 25.632 4.537 25.656 ;
     RECT  4.669 17.088 4.753 17.112 ;
     RECT  4.453 36.624 4.979 41.016 ;
     RECT  4.979 36.624 5.101 37.08 ;
     RECT  5.101 36.576 5.213 37.08 ;
     RECT  4.979 38.16 5.501 41.016 ;
     RECT  5.213 37.056 5.933 37.08 ;
     RECT  5.501 38.16 6.613 39.96 ;
     RECT  6.613 37.968 7.045 39.96 ;
     RECT  5.501 40.992 7.045 41.016 ;
     RECT  7.045 37.968 7.657 41.016 ;
     RECT  7.657 37.968 7.808 41.208 ;
     RECT  7.808 2.148 7.811 41.208 ;
     RECT  7.811 2.148 7.912 41.052 ;
     RECT  7.693 42.24 7.916 42.264 ;
     RECT  7.912 2.418 8.104 41.016 ;
     RECT  7.916 42.192 8.195 42.264 ;
     RECT  8.195 42.192 8.675 42.216 ;
     RECT  8.104 37.968 8.777 39.768 ;
     RECT  8.104 40.992 9.068 41.016 ;
     RECT  9.068 40.992 9.155 41.64 ;
     RECT  8.777 38.112 9.781 39.768 ;
     RECT  9.155 40.992 9.781 41.016 ;
     RECT  9.781 38.112 10.019 41.016 ;
     RECT  10.019 40.992 10.177 41.016 ;
     RECT  10.177 40.992 10.213 41.64 ;
     RECT  10.213 40.992 10.307 42.216 ;
     RECT  10.019 38.112 10.541 39.768 ;
     RECT  10.307 40.992 10.691 41.64 ;
     RECT  10.691 40.992 11.581 41.016 ;
     RECT  10.541 38.112 11.941 39.624 ;
     RECT  11.941 37.968 12.092 39.624 ;
     RECT  11.581 40.704 12.092 41.016 ;
     RECT  12.092 37.968 12.179 41.016 ;
     RECT  12.179 40.704 13.148 41.016 ;
     RECT  12.179 37.968 13.208 39.624 ;
     RECT  13.148 40.704 13.208 41.208 ;
     RECT  13.208 2.148 13.235 41.208 ;
     RECT  13.235 2.148 13.312 41.16 ;
     RECT  13.312 2.418 13.504 41.16 ;
     RECT  13.504 37.584 13.523 41.16 ;
     RECT  13.628 42.192 13.715 42.216 ;
     RECT  14.713 42.192 14.867 42.216 ;
     RECT  13.523 37.584 15.613 41.016 ;
     RECT  15.613 37.584 15.731 41.64 ;
     RECT  15.731 41.616 16.019 41.64 ;
     RECT  15.731 37.584 16.211 40.488 ;
     RECT  16.211 37.584 17.557 39.768 ;
     RECT  16.873 40.992 17.557 41.016 ;
     RECT  18.205 42.192 18.323 42.216 ;
     RECT  17.557 37.584 18.608 41.016 ;
     RECT  18.608 2.148 18.661 41.052 ;
     RECT  18.661 2.148 18.712 41.208 ;
     RECT  18.712 2.418 18.785 41.208 ;
     RECT  18.785 2.418 18.904 41.16 ;
     RECT  18.904 40.896 19.036 41.16 ;
     RECT  18.904 22.848 19.037 23.064 ;
     RECT  18.904 21.072 19.657 21.096 ;
     RECT  18.904 19.92 19.765 19.944 ;
     RECT  19.036 40.896 19.859 41.016 ;
     RECT  18.904 37.392 20.101 39.624 ;
     RECT  19.037 23.04 20.396 23.064 ;
     RECT  20.101 36.576 20.437 39.624 ;
     RECT  20.396 23.04 20.483 23.592 ;
     RECT  20.437 35.904 20.524 39.624 ;
     RECT  20.545 22.896 20.945 22.92 ;
     RECT  19.859 40.992 21.193 41.016 ;
     RECT  21.193 40.704 21.269 41.016 ;
     RECT  20.524 36.672 21.539 39.624 ;
     RECT  21.539 37.488 21.637 39.624 ;
     RECT  21.269 40.704 21.637 40.728 ;
     RECT  21.637 37.488 21.773 40.728 ;
     RECT  22.057 31.344 22.141 31.368 ;
     RECT  21.773 40.704 22.309 40.728 ;
     RECT  21.773 37.488 22.645 39.624 ;
     RECT  22.309 40.704 22.691 41.016 ;
     RECT  22.633 31.872 22.717 31.896 ;
     RECT  22.645 37.344 22.889 39.624 ;
     RECT  22.691 40.992 23.797 41.016 ;
     RECT  22.069 21.12 24.008 21.144 ;
     RECT  22.889 37.344 24.008 39.336 ;
     RECT  23.797 40.464 24.008 41.016 ;
     RECT  24.008 2.148 24.112 41.052 ;
     RECT  24.112 2.418 24.14 41.052 ;
     RECT  24.14 2.418 24.227 41.16 ;
     RECT  24.227 2.418 24.304 41.016 ;
     RECT  23.821 42.192 24.707 42.216 ;
     RECT  24.304 40.464 25.229 41.016 ;
     RECT  24.304 37.344 25.445 39.384 ;
     RECT  25.445 38.4 25.913 39.384 ;
     RECT  25.229 40.992 26.197 41.016 ;
     RECT  26.197 40.992 26.339 41.64 ;
     RECT  25.445 37.344 26.773 37.368 ;
     RECT  25.913 38.4 26.773 39.192 ;
     RECT  26.737 42.192 27.011 42.216 ;
     RECT  26.773 37.344 27.277 39.192 ;
     RECT  27.277 37.344 27.529 39.624 ;
     RECT  27.529 37.344 27.613 39.912 ;
     RECT  26.339 40.992 28.748 41.016 ;
     RECT  28.748 40.608 29.365 41.016 ;
     RECT  24.304 21.12 29.408 21.144 ;
     RECT  27.613 37.344 29.408 39.624 ;
     RECT  29.365 40.608 29.408 41.208 ;
     RECT  29.408 2.148 29.507 41.208 ;
     RECT  29.507 2.148 29.512 41.052 ;
     RECT  29.512 2.418 29.704 41.016 ;
     RECT  29.704 37.584 30.275 39.192 ;
     RECT  30.275 37.584 30.557 38.904 ;
     RECT  29.612 42.192 30.851 42.216 ;
     RECT  30.557 37.584 32.173 38.856 ;
     RECT  29.704 40.464 32.195 41.016 ;
     RECT  32.173 37.584 32.789 39.336 ;
     RECT  32.195 40.992 33.637 41.016 ;
     RECT  32.789 37.584 34.165 38.856 ;
     RECT  33.637 40.464 34.405 41.016 ;
     RECT  34.165 37.44 34.585 38.856 ;
     RECT  29.704 21.12 34.808 21.144 ;
     RECT  34.585 37.44 34.808 39 ;
     RECT  34.405 40.464 34.808 41.64 ;
     RECT  34.808 2.148 34.912 41.64 ;
     RECT  34.912 2.418 35.027 41.64 ;
     RECT  35.027 2.418 35.104 41.016 ;
     RECT  35.104 37.44 35.417 39.24 ;
     RECT  35.417 37.584 35.741 39.24 ;
     RECT  35.104 40.464 36.851 41.016 ;
     RECT  36.851 40.992 37.249 41.016 ;
     RECT  37.249 40.992 37.577 41.64 ;
     RECT  37.577 41.616 37.715 41.64 ;
     RECT  37.861 40.464 37.973 40.488 ;
     RECT  38.581 40.992 38.725 41.016 ;
     RECT  38.293 42.192 38.725 42.216 ;
     RECT  35.741 38.112 38.909 39.24 ;
     RECT  38.909 38.112 39.203 38.952 ;
     RECT  38.725 40.992 39.347 42.216 ;
     RECT  39.347 40.992 39.781 41.208 ;
     RECT  35.104 21.12 40.208 21.144 ;
     RECT  39.203 38.112 40.208 38.76 ;
     RECT  39.781 40.464 40.208 41.208 ;
     RECT  40.208 2.148 40.211 41.208 ;
     RECT  40.211 2.148 40.312 41.052 ;
     RECT  39.347 42.192 40.499 42.216 ;
     RECT  40.312 2.418 40.504 41.016 ;
     RECT  40.504 38.256 40.565 38.28 ;
     RECT  40.504 40.56 40.691 41.016 ;
     RECT  40.691 40.992 40.883 41.016 ;
     RECT  40.504 21.12 43.02 22.056 ;
    LAYER M5 ;
     RECT  2.4 2.137 2.52 2.151 ;
     RECT  7.8 2.137 7.92 2.151 ;
     RECT  13.2 2.137 13.32 2.151 ;
     RECT  18.6 2.137 18.72 2.151 ;
     RECT  24 2.137 24.12 2.151 ;
     RECT  29.4 2.137 29.52 2.151 ;
     RECT  34.8 2.137 34.92 2.151 ;
     RECT  40.2 2.137 40.32 2.151 ;
     RECT  4.32 16.165 4.344 17.077 ;
     RECT  18.6 2.151 18.912 19.909 ;
     RECT  18.6 19.909 19.752 23.029 ;
     RECT  4.32 17.077 4.728 28.453 ;
     RECT  22.08 21.109 22.104 31.379 ;
     RECT  22.656 31.861 22.68 37.379 ;
     RECT  29.4 2.151 29.712 37.429 ;
     RECT  34.8 2.151 35.112 37.429 ;
     RECT  3.936 28.453 4.728 37.573 ;
     RECT  18.6 23.029 20.472 38.005 ;
     RECT  2.4 2.151 2.712 38.101 ;
     RECT  3.936 37.573 4.968 38.101 ;
     RECT  7.8 2.151 8.112 38.149 ;
     RECT  29.28 37.429 29.712 38.149 ;
     RECT  34.176 37.429 35.112 38.195 ;
     RECT  18.048 38.005 20.472 38.435 ;
     RECT  34.608 38.195 35.112 38.675 ;
     RECT  18.048 38.435 19.752 38.677 ;
     RECT  28.512 38.149 29.712 38.677 ;
     RECT  14.496 38.101 14.52 38.725 ;
     RECT  34.8 38.675 35.112 38.725 ;
     RECT  2.4 38.101 4.968 38.819 ;
     RECT  6.288 38.437 6.312 38.819 ;
     RECT  11.952 37.957 11.976 38.819 ;
     RECT  17.616 38.677 19.752 38.819 ;
     RECT  21.504 36.661 21.528 38.819 ;
     RECT  27.552 38.677 29.712 38.819 ;
     RECT  29.28 38.819 29.712 38.869 ;
     RECT  39.168 38.533 39.192 38.963 ;
     RECT  14.496 38.725 14.712 39.107 ;
     RECT  29.28 38.869 30.264 39.203 ;
     RECT  34.8 38.725 36.024 39.251 ;
     RECT  24 2.151 24.312 39.301 ;
     RECT  14.688 39.107 14.712 39.347 ;
     RECT  29.28 39.203 29.712 39.635 ;
     RECT  27.552 38.819 27.576 39.923 ;
     RECT  2.4 38.819 4.824 40.453 ;
     RECT  7.68 38.149 8.112 40.453 ;
     RECT  13.2 2.151 13.512 40.453 ;
     RECT  23.328 39.301 24.312 40.453 ;
     RECT  29.4 39.635 29.712 40.453 ;
     RECT  34.8 39.251 35.112 40.453 ;
     RECT  40.2 2.151 40.512 40.453 ;
     RECT  39.792 40.453 40.512 40.549 ;
     RECT  29.4 40.453 32.184 40.597 ;
     RECT  12.144 40.453 12.168 40.693 ;
     RECT  13.2 40.453 16.2 40.693 ;
     RECT  21.648 40.453 21.672 40.693 ;
     RECT  23.328 40.453 25.176 40.693 ;
     RECT  17.616 38.819 18.912 40.885 ;
     RECT  2.256 40.453 5.16 40.981 ;
     RECT  7.104 40.453 8.112 40.981 ;
     RECT  9.984 40.693 10.008 40.981 ;
     RECT  11.664 40.693 16.2 40.981 ;
     RECT  17.616 40.885 19.848 40.981 ;
     RECT  21.456 40.693 21.672 40.981 ;
     RECT  22.656 40.693 25.176 40.981 ;
     RECT  28.8 40.597 32.184 40.981 ;
     RECT  33.648 40.453 36.84 40.981 ;
     RECT  37.872 40.453 37.896 40.981 ;
     RECT  39.792 40.549 40.68 40.981 ;
     RECT  2.256 40.981 40.872 43.024 ;
     RECT  2.712 28.453 3.936 38.101 ;
     RECT  22.68 31.861 24 37.379 ;
     RECT  20.472 36.661 21.504 38.435 ;
     RECT  21.528 36.661 22.656 37.379 ;
     RECT  11.976 37.957 13.2 38.819 ;
     RECT  13.512 38.101 14.496 39.107 ;
     RECT  4.968 38.437 6.288 38.819 ;
     RECT  6.312 38.437 7.68 38.819 ;
     RECT  39.192 38.533 40.2 38.963 ;
     RECT  39.792 38.963 40.2 40.453 ;
     RECT  13.512 39.107 14.688 39.347 ;
     RECT  29.712 39.203 30.264 40.453 ;
     RECT  35.112 39.251 36.024 40.453 ;
     RECT  13.512 39.347 14.712 40.453 ;
     RECT  29.28 39.635 29.4 40.597 ;
     RECT  27.552 39.923 27.576 40.597 ;
     RECT  12.168 40.453 13.2 40.693 ;
     RECT  16.2 40.453 17.616 40.981 ;
     RECT  32.184 40.453 33.648 40.981 ;
     RECT  36.84 40.453 37.872 40.981 ;
     RECT  27.552 40.597 28.8 40.981 ;
     RECT  21.672 40.693 22.656 40.981 ;
  END
END dsfd_vm_static_write_capture128_W
END LIBRARY
